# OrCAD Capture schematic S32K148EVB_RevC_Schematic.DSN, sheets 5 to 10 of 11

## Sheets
5 05. OPEN SDA: size D; company: Freescale Semiconductor; note: SCH-29642 PDF: SPF-29642
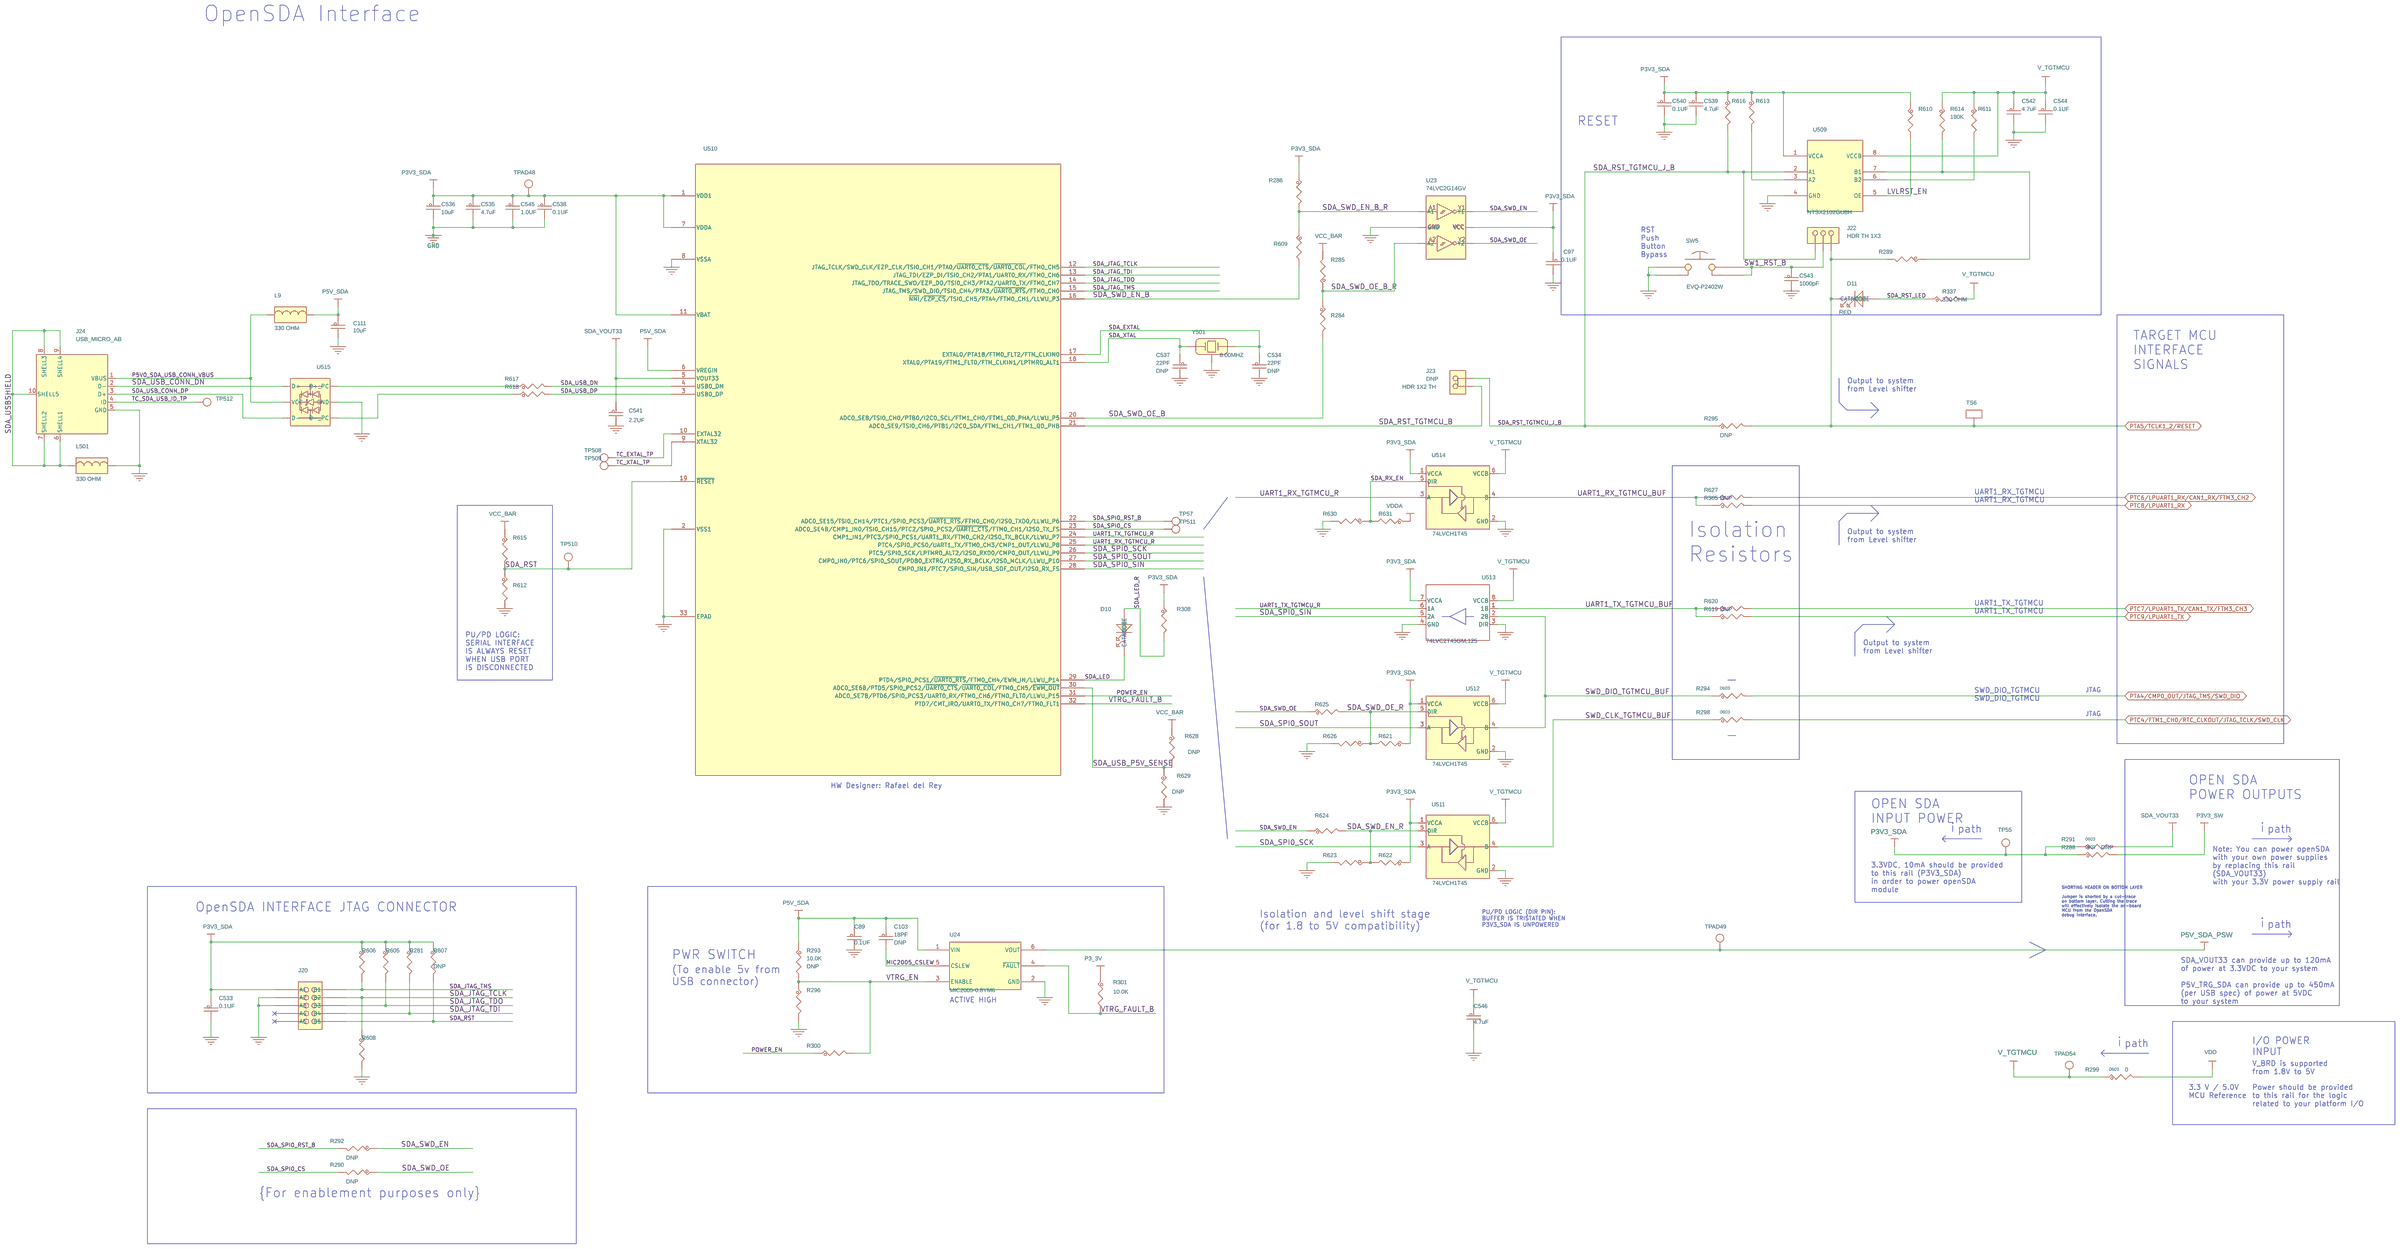
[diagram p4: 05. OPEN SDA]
6 06. ETHERNET: size C; note: SCH-29642 PDF: SPF-29642
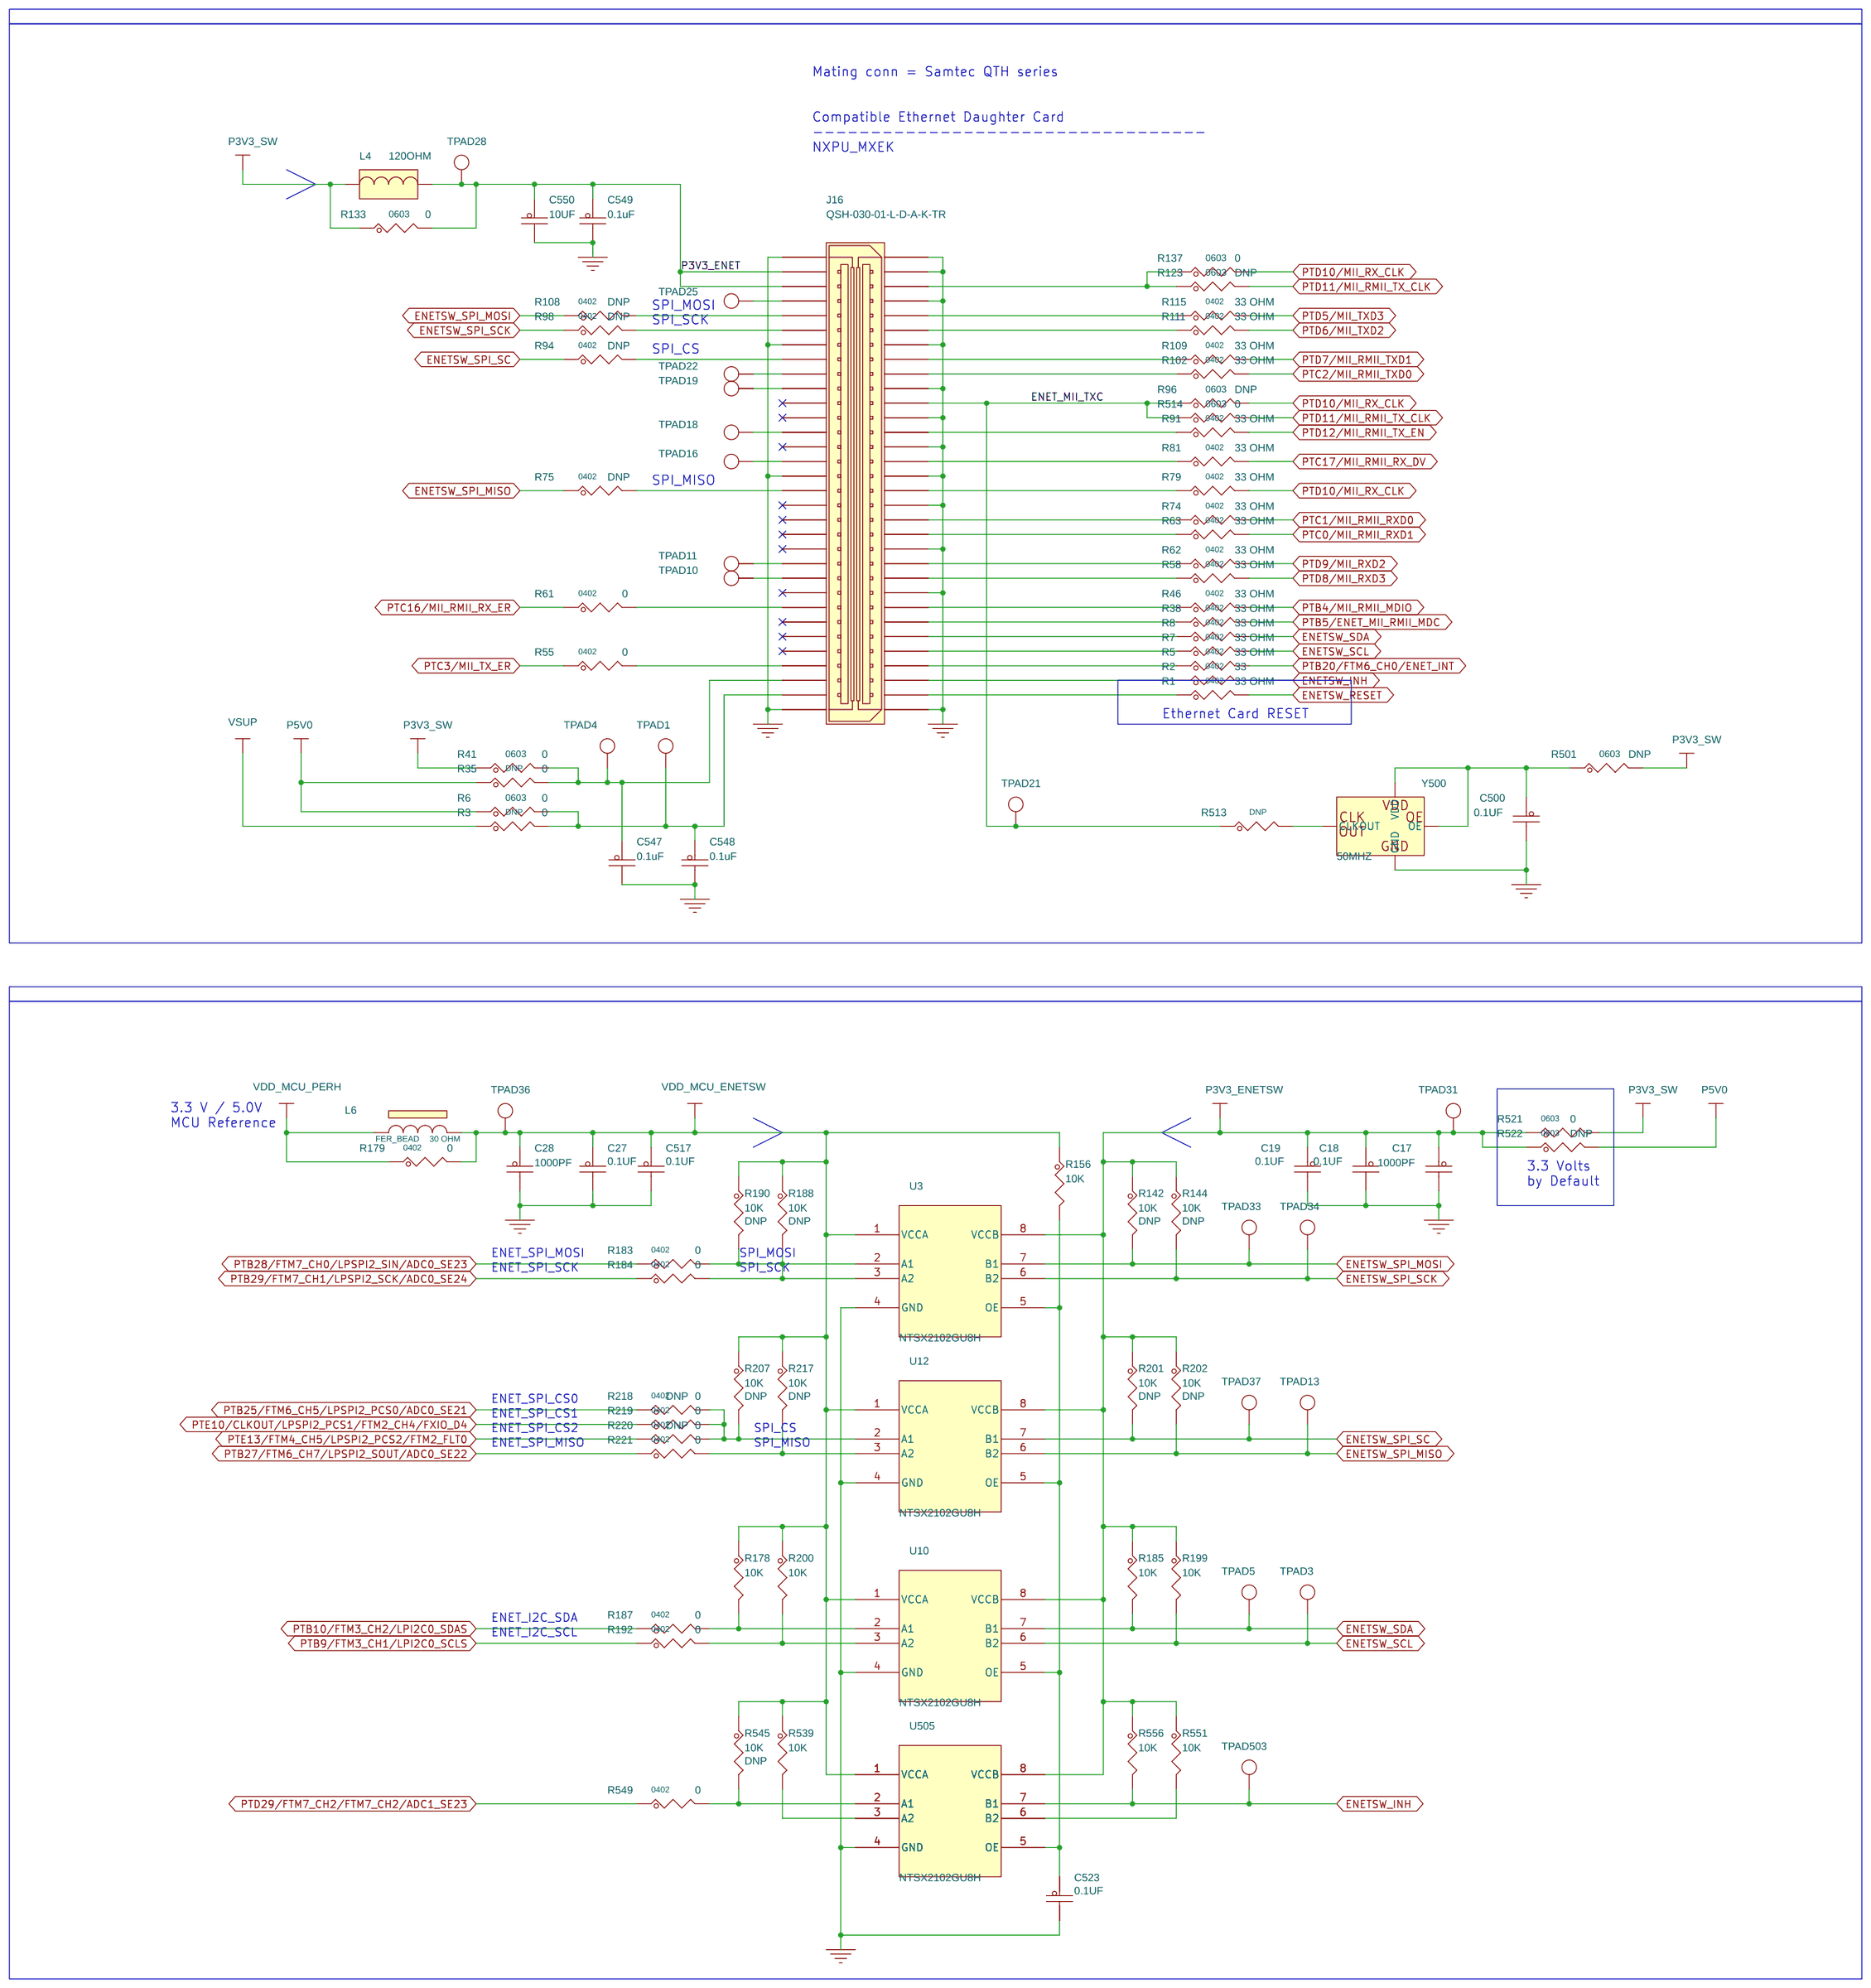
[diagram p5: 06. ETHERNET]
7 07. HYPERFLASH: size B; note: SCH-29642 PDF: SPF-29642
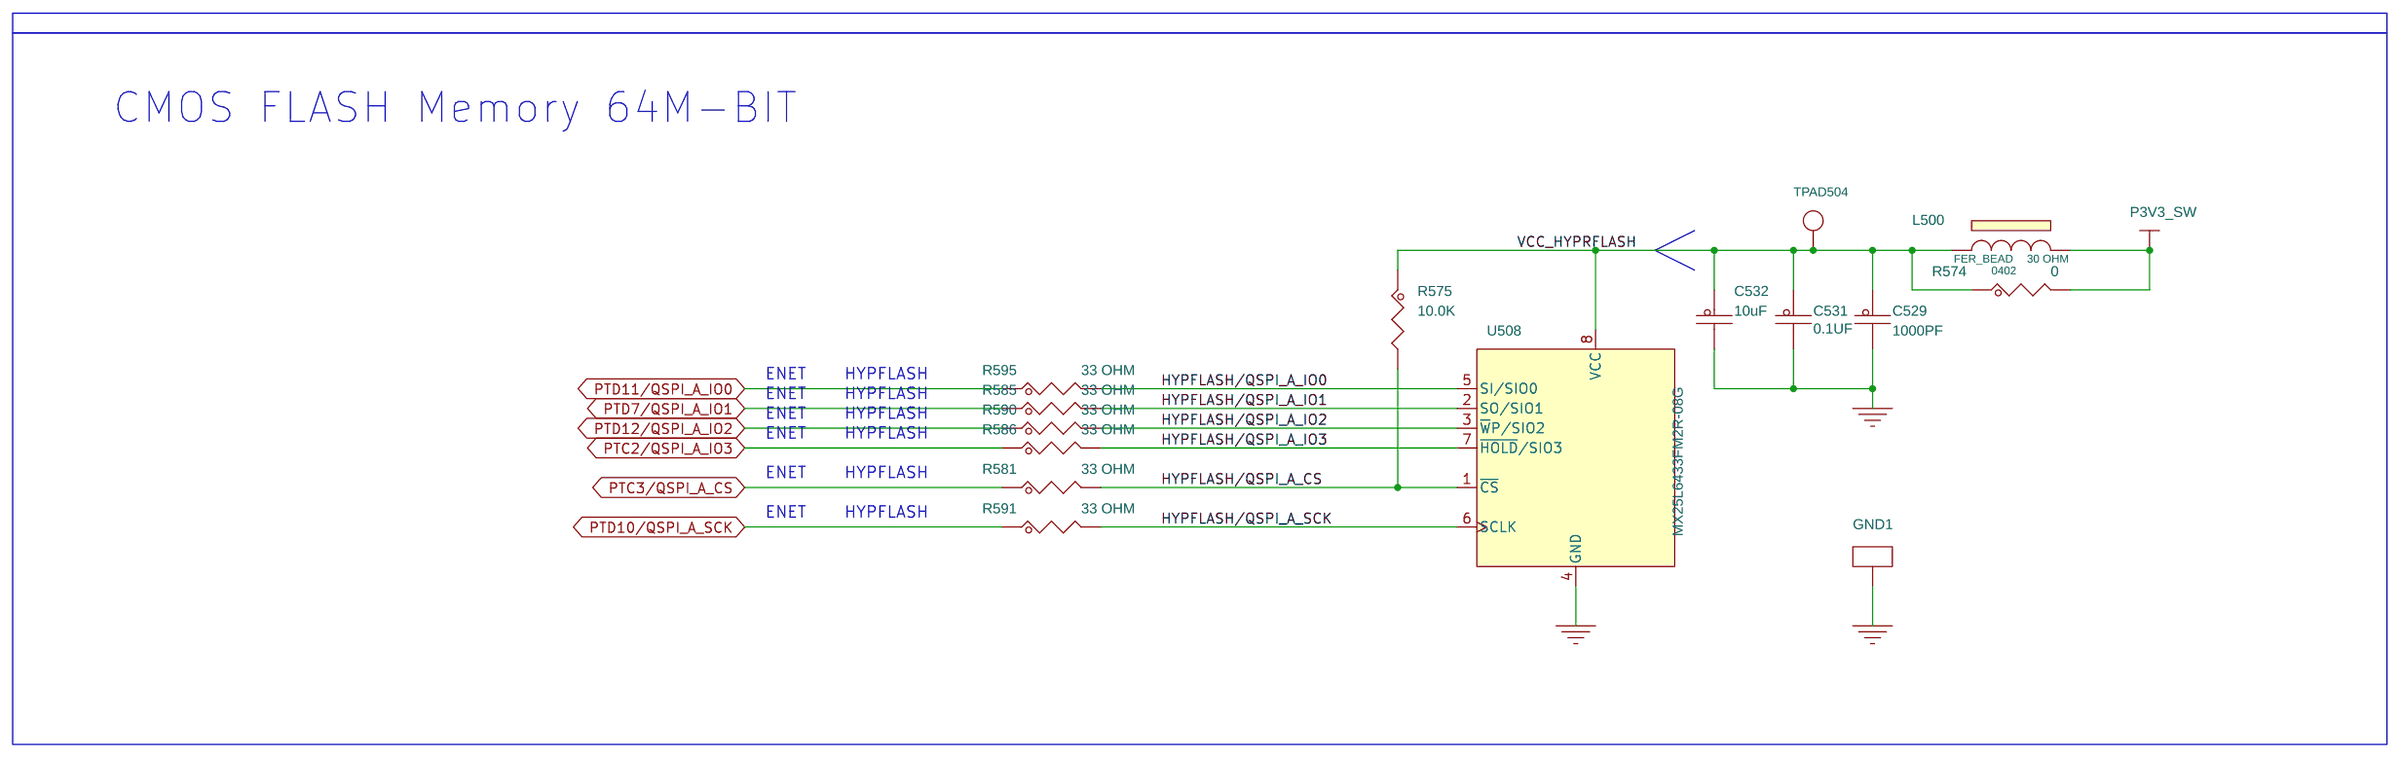
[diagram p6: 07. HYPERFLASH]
8 10. TOUCHPAD: size B; note: SCH-29642 PDF: SPF-29642
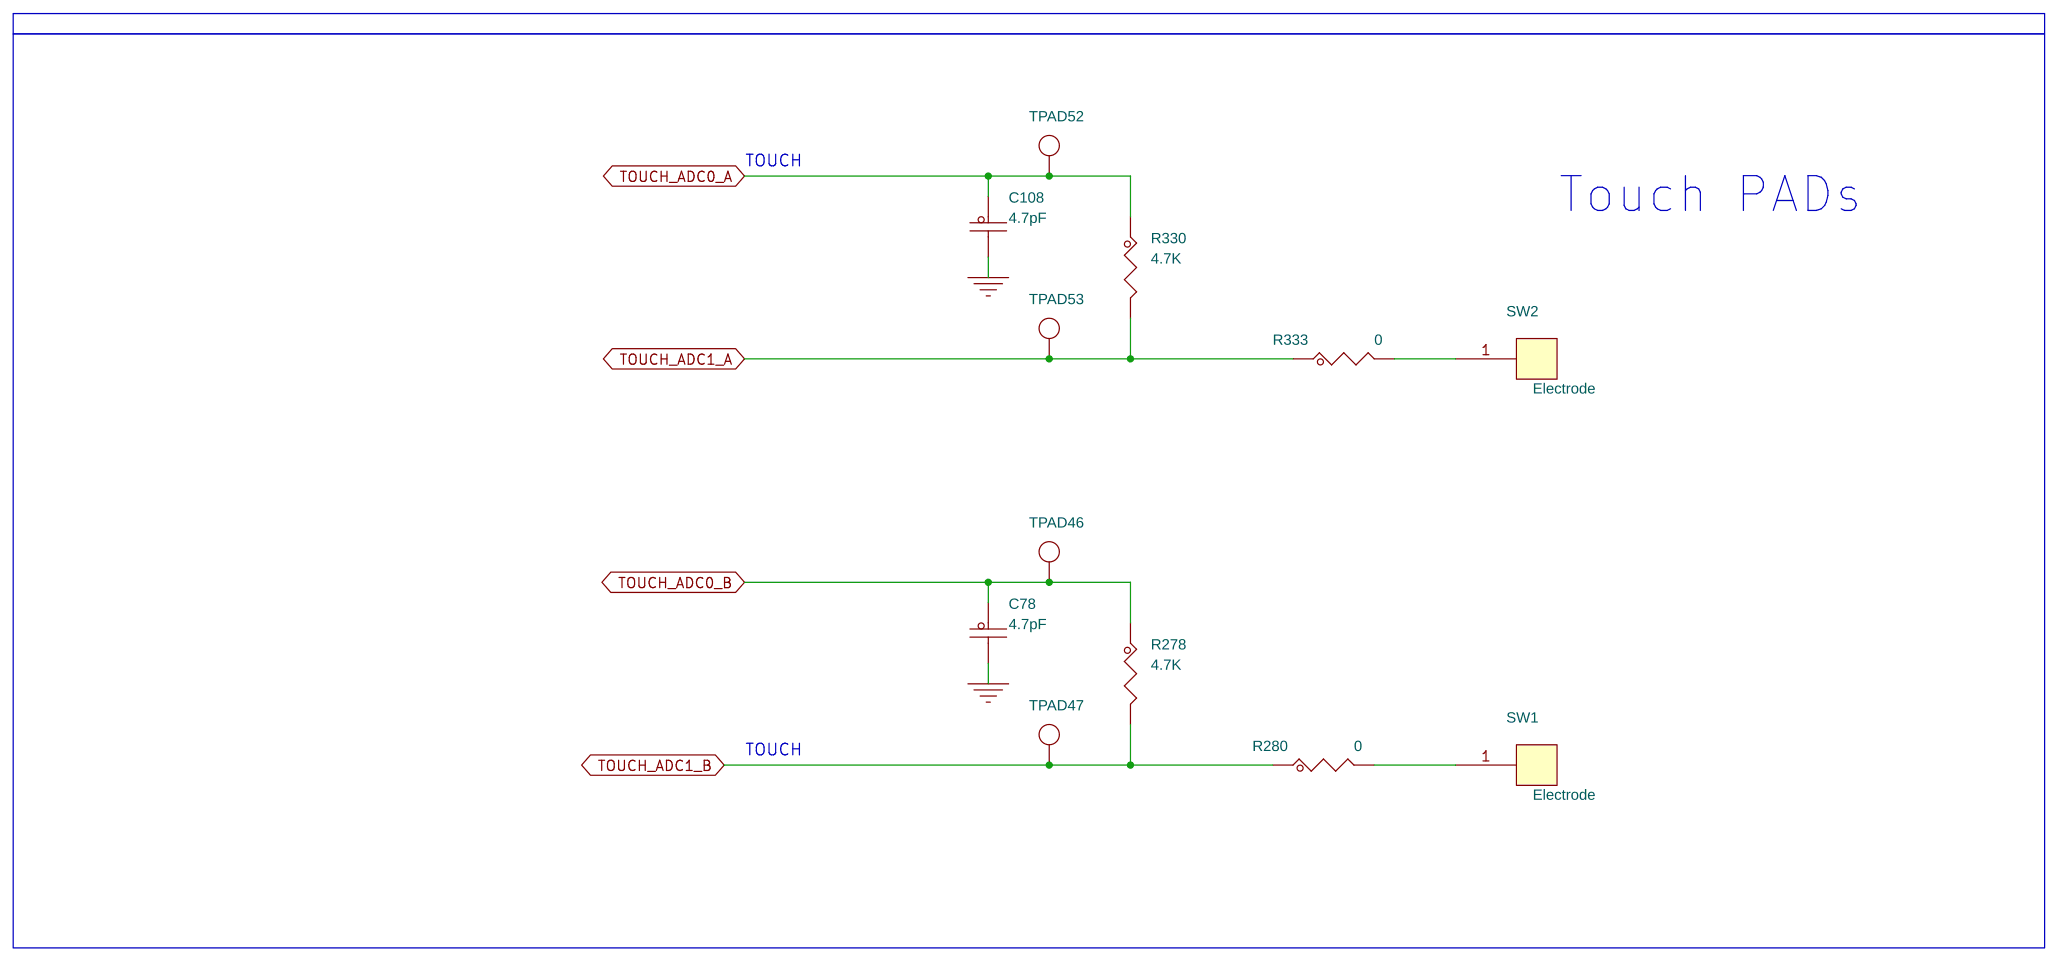
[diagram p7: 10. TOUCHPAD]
9 11. USER PHERP: size B; company: Freescale Semiconductor; note: SCH-29642 PDF: SPF-29642
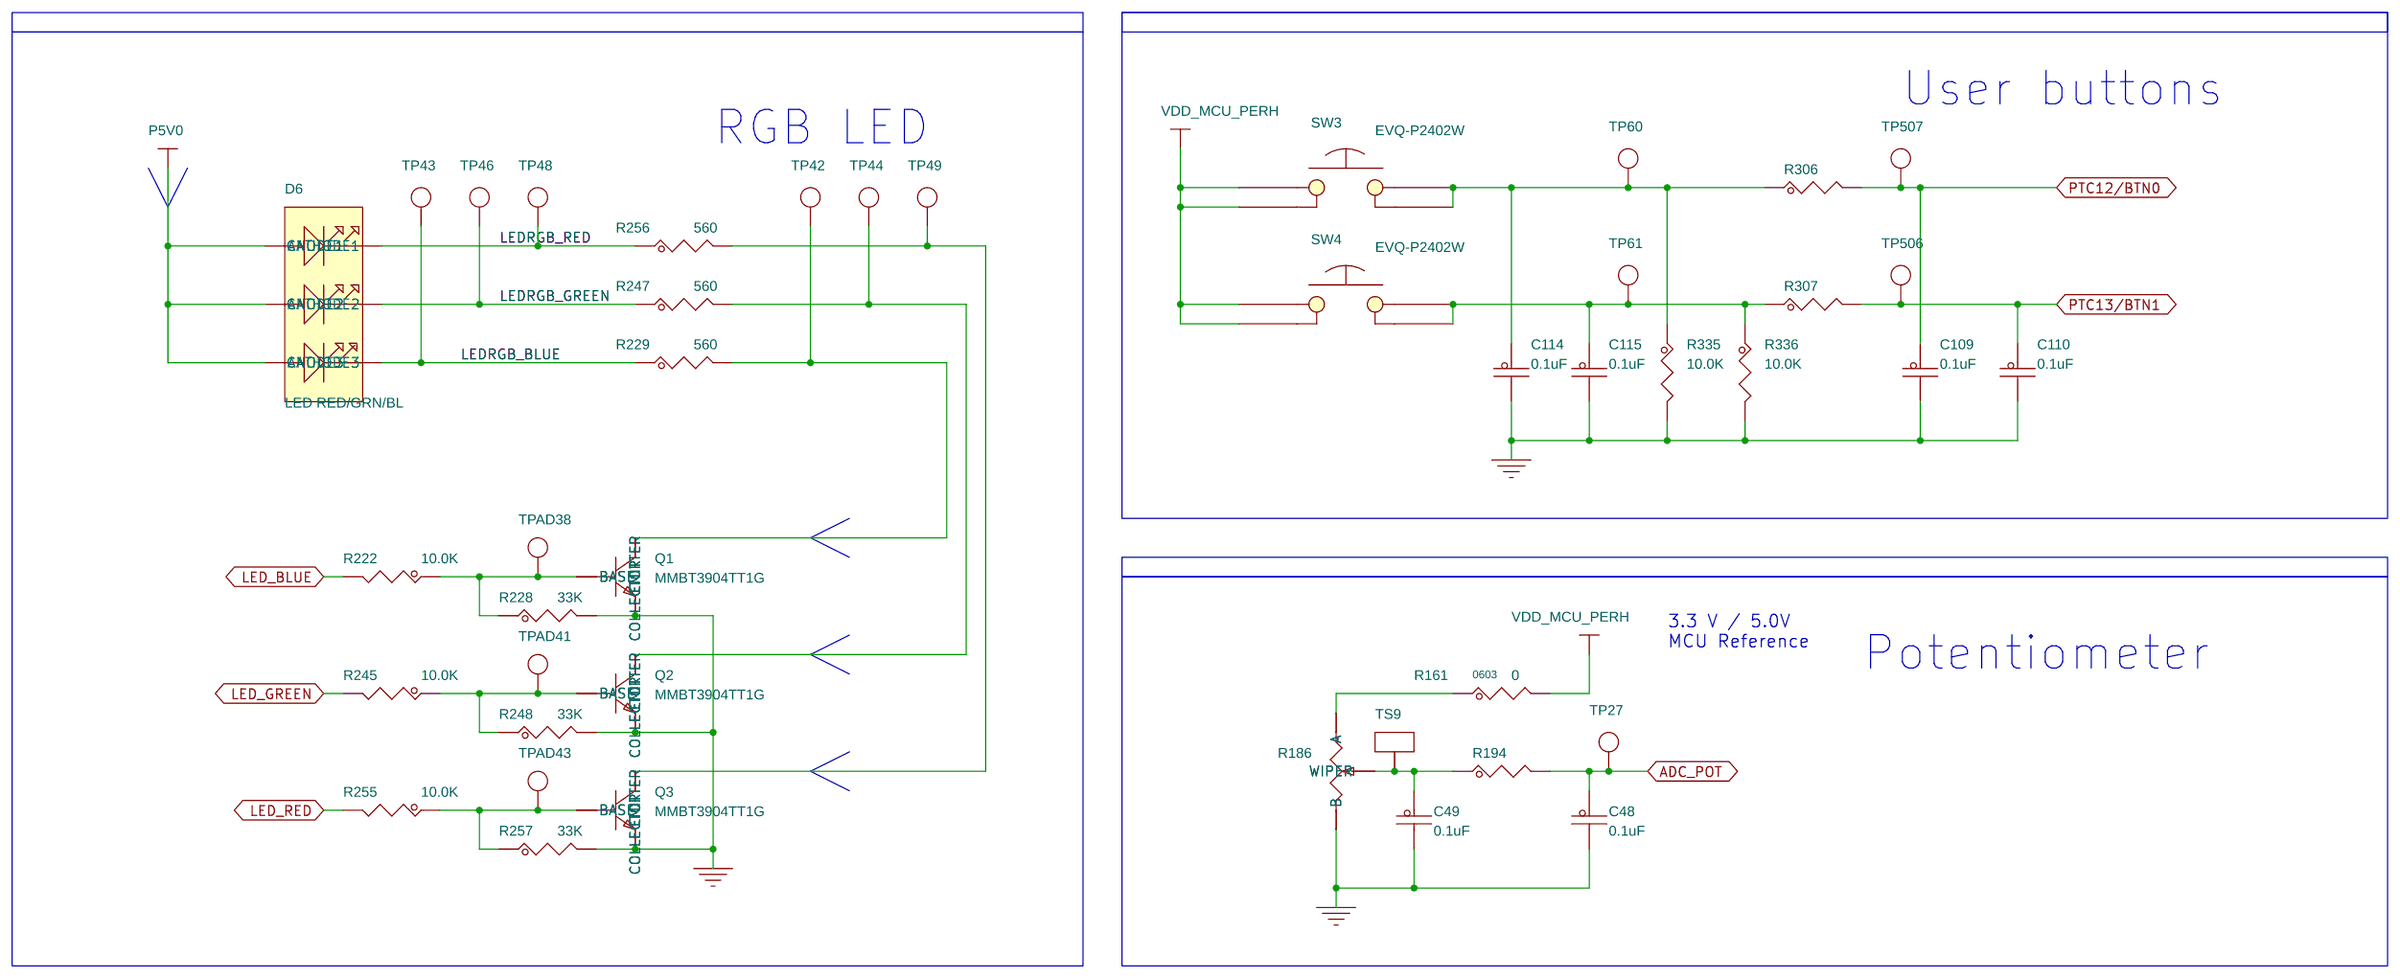
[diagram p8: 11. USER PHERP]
10 01. TITLE/NOTE: company: Freescale Semiconductor; note: SCH-29642 PDF: SPF-29642

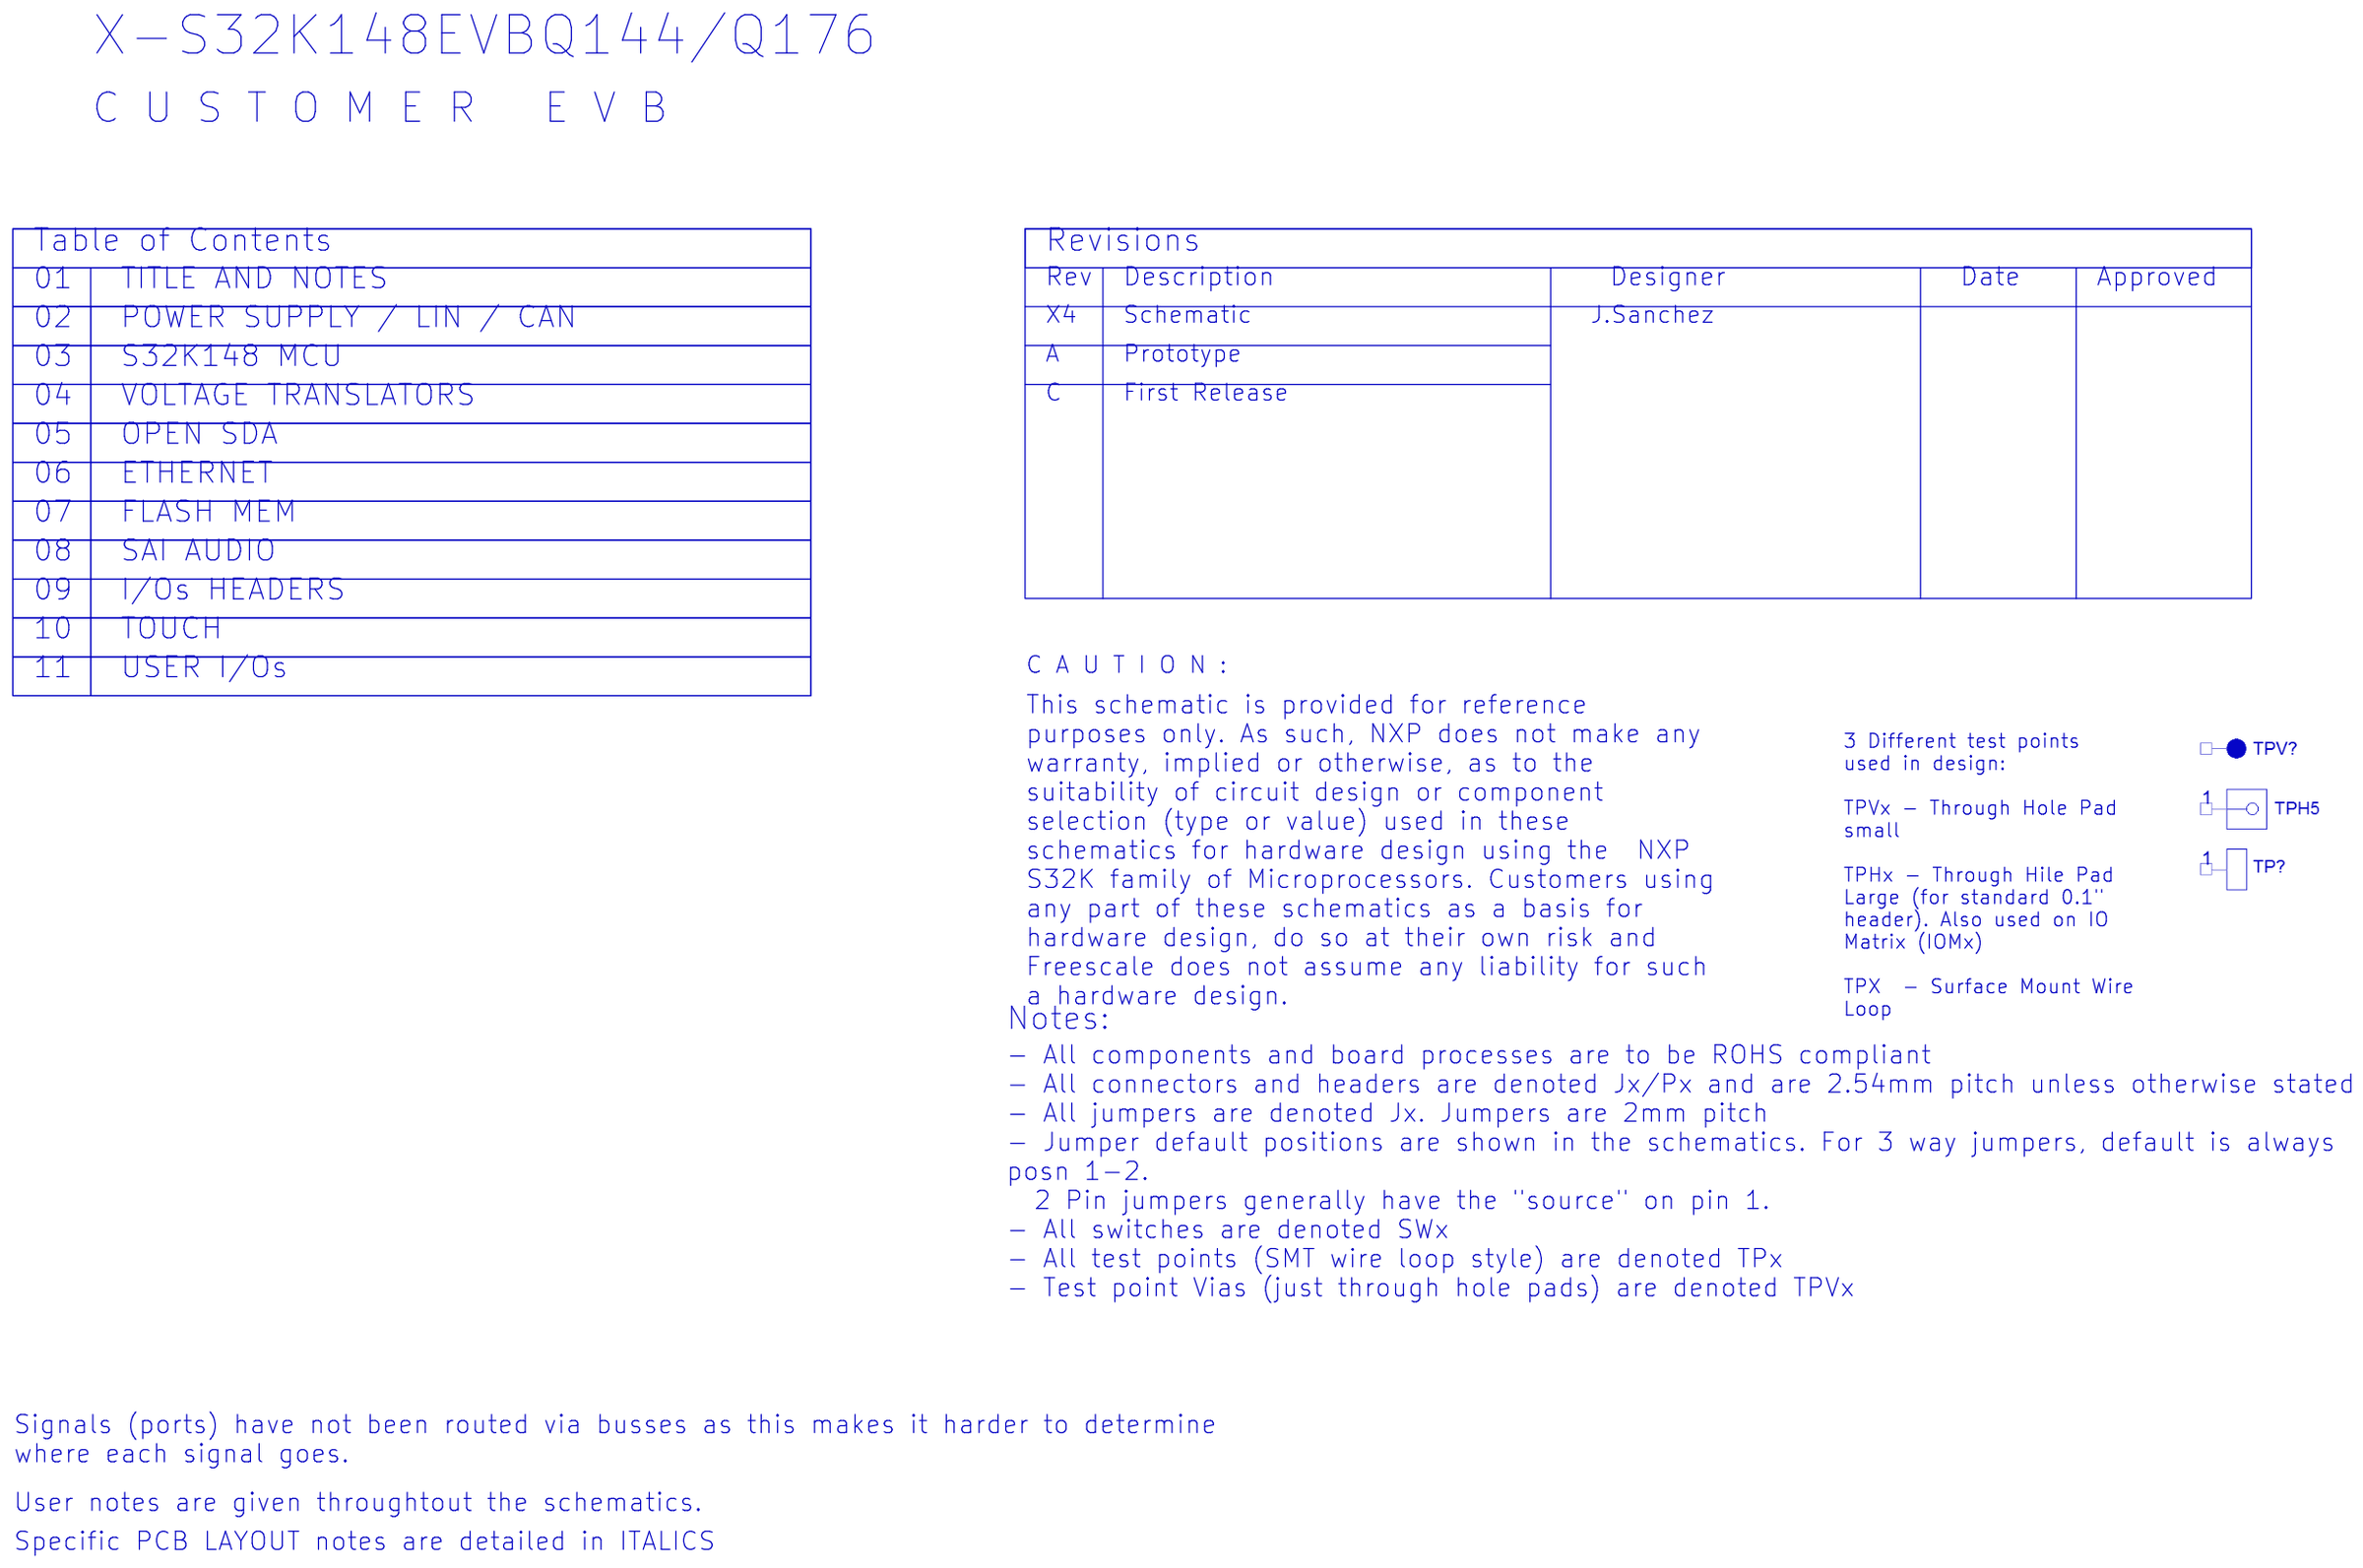
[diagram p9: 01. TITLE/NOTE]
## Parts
sheet 05. OPEN SDA
C89  0.1UF  [CC0402_25]
C97  0.1UF  [CC0402_25]
C103  18PF  [CC0603_OV]
C111  10uF  [CC0402_25]
C533  0.1UF  [CC0402_25]
C534  22PF  [CC0402_25]
C535  4.7uF  [CC0402_25]
C536  10uF  [CC0603_OV]
C537  22PF  [CC0402_25]
C538  0.1UF  [CC0402_25]
C539  4.7uF  [CC0402_25]
C540  0.1UF  [CC0402_25]
C541  2.2UF  [CC0603_OV]
C542  4.7uF  [CC0402_25]
C543  1000pF  [CC0402_25]
C544  0.1UF  [CC0402_25]
C545  1.0UF  [CC0402_25]
C546  4.7uF  [CC0402_25]
D10  LED GREEN  [LED_0603]
D11  RED  [LED_0603]
J20  HDR 2X5  [CON_2RH_10_50]
J22  HDR TH 1X3  [HDR103]
J23  HDR 1X2 TH  [SH_HDR102_BOTTOM]
J24  USB_MICRO_AB  [con_microab_10f_25_sm_ra]
L9  330 OHM  [ind_1608]
L501  330 OHM  [ind_1608]
R281  10.0K  [RC0402_25]
R284  0  [RC0402_25]
R285  10.0K  [RC0402_25]
R286  10.0K  [RC0402_25]
R288  0  [RC0603]
R289  0  [RC0402_25]
R290  0  [RC0402_25]
R291  0  [RC0603]
R292  0  [RC0402_25]
R293  10.0K  [RC0402_25]
R294  0  [RC0603]
R295  0  [RC0402_25]
R296  15K  [RC0402_25]
R298  0  [RC0603]
R299  0  [RC0603]
R300  1.0K  [RC0402_25]
R301  10.0K  [RC0402_25]
R305  0  [RC0402_25]
R308  220  [RC0603_OV]
R337  330 OHM  [RC0402_25]
R605  10.0K  [RC0402_25]
R606  10.0K  [RC0402_25]
R607  10.0K  [RC0402_25]
R608  10.0K  [RC0402_25]
R609  0  [RC0402_25]
R610  4.7K  [RC0402_25]
R611  10.0K  [RC0402_25]
R612  10.0K  [RC0402_25]
R613  10.0K  [RC0402_25]
R614  180K  [RC0402_25]
R615  4.7K  [RC0402_25]
R616  10.0K  [RC0402_25]
R617  33  [RC0402_25]
R618  33  [RC0402_25]
R619  0  [RC0402_25]
R620  0  [RC0402_25]
R621  4.7K  [RC0402_25]
R622  4.7K  [RC0402_25]
R623  10.0K  [RC0402_25]
R624  0  [RC0402_25]
R625  0  [RC0402_25]
R626  10.0K  [RC0402_25]
R627  0  [RC0402_25]
R628  4.7K  [RC0402_25]
R629  10.0K  [RC0402_25]
R630  10.0K  [RC0402_25]
R631  4.7K  [RC0402_25]
SW5  EVQ-P2402W  [sw4_spst_4p8X3p6_2p5]
TP55  TPAD_030  [TPAD_030]
TP57  TPAD_030  [TPAD_030]
TP508  TPAD_030  [TPAD_030]
TP509  TPAD_030  [TPAD_030]
TP510  TPAD_030  [TPAD_030]
TP511  TPAD_030  [TPAD_030]
TP512  TPAD_030  [TPAD_030]
TPAD48  TPAD_030  [TPAD_030]
TPAD49  TPAD_030  [TPAD_030]
TPAD54  TPAD_030  [TPAD_030]
TS6  TESTLOOP  [testpoint_135_070mil]
U23  74LVC2G14GV  [SC74_6P_1P7X3P1]
U24  MIC2005-0.8YM6  [SOT23-6_a]
U509  NTSX2102GU8H  [xqfn8_1p45x1p25mm]
U510  MK20DX128VFM5  [QFN32_S142EP]
U511  74LVCH1T45  [udfn6_1x1p5mm]
U512  74LVCH1T45  [udfn6_1x1p5mm]
U513  74LVC2T45GM,125  [qfn8_1p6x1p6mm]
U514  74LVCH1T45  [udfn6_1x1p5mm]
U515  RClamp0502A.TCT  [sot666]
Y501  8.00MHZ  [xtal3_3p35x1p45_sm]
sheet 06. ETHERNET
C17  1000PF  [CC0603_OV]
C18  0.1UF  [CC0603_OV]
C19  0.1UF  [CC0603_OV]
C27  0.1UF  [CC0603_OV]
C28  1000PF  [CC0603_OV]
C500  0.1UF  [CC0603]
C517  0.1UF  [CC0603_OV]
C523  0.1UF  [CC0603_OV]
C547  0.1uF  [CC0402_25]
C548  0.1uF  [CC0402_25]
C549  0.1uF  [CC0402_25]
C550  10UF  [CC0805_OV]
J16  QSH-030-01-L-D-A-K-TR  [CON_60S_QSH_SM_A]
L4  120OHM  [IND_0603]
L6  30 OHM  [IND_0402]
R1  33 OHM  [RC0402_25]
R2  33  [RC0402_25]
R3  0  [RC0603]
R5  33 OHM  [RC0402_25]
R6  0  [RC0603]
R7  33 OHM  [RC0402_25]
R8  33 OHM  [RC0402_25]
R35  0  [RC0603]
R38  33 OHM  [RC0402_25]
R41  0  [RC0603]
R46  33 OHM  [RC0402_25]
R55  0  [RC0402_25]
R58  33 OHM  [RC0402_25]
R61  0  [RC0402_25]
R62  33 OHM  [RC0402_25]
R63  33 OHM  [RC0402_25]
R74  33 OHM  [RC0402_25]
R75  0  [RC0402_25]
R79  33 OHM  [RC0402_25]
R81  33 OHM  [RC0402_25]
R91  33 OHM  [RC0402_25]
R94  0  [RC0402_25]
R96  0  [RC0603]
R98  0  [RC0402_25]
R102  33 OHM  [RC0402_25]
R108  0  [RC0402_25]
R109  33 OHM  [RC0402_25]
R111  33 OHM  [RC0402_25]
R115  33 OHM  [RC0402_25]
R123  0  [RC0603]
R133  0  [RC0603]
R137  0  [RC0603]
R142  10K  [RC0603_OV]
R144  10K  [RC0603_OV]
R156  10K  [RC0603_OV]
R178  10K  [RC0603_OV]
R179  0  [RC0402_25]
R183  0  [RC0402_25]
R184  0  [RC0402_25]
R185  10K  [RC0603_OV]
R187  0  [RC0402_25]
R188  10K  [RC0603_OV]
R190  10K  [RC0603_OV]
R192  0  [RC0402_25]
R199  10K  [RC0603_OV]
R200  10K  [RC0603_OV]
R201  10K  [RC0603_OV]
R202  10K  [RC0603_OV]
R207  10K  [RC0603_OV]
R217  10K  [RC0603_OV]
R218  0  [RC0402_25]
R219  0  [RC0402_25]
R220  0  [RC0402_25]
R221  0  [RC0402_25]
R501  0  [RC0603]
R513  0  [RC0603]
R514  0  [RC0603]
R521  0  [RC0603]
R522  0  [RC0603]
R539  10K  [RC0603_OV]
R545  10K  [RC0603_OV]
R549  0  [RC0402_25]
R551  10K  [RC0603_OV]
R556  10K  [RC0603_OV]
TPAD1  TPAD_030  [TPAD_030]
TPAD3  TPAD_030  [TPAD_030]
TPAD4  TPAD_030  [TPAD_030]
TPAD5  TPAD_030  [TPAD_030]
TPAD10  TPAD_030  [TPAD_030]
TPAD11  TPAD_030  [TPAD_030]
TPAD13  TPAD_030  [TPAD_030]
TPAD16  TPAD_030  [TPAD_030]
TPAD18  TPAD_030  [TPAD_030]
TPAD19  TPAD_030  [TPAD_030]
TPAD21  TPAD_030  [TPAD_030]
TPAD22  TPAD_030  [TPAD_030]
TPAD25  TPAD_030  [TPAD_030]
TPAD28  TPAD_030  [TPAD_030]
TPAD31  TPAD_030  [TPAD_030]
TPAD33  TPAD_030  [TPAD_030]
TPAD34  TPAD_030  [TPAD_030]
TPAD36  TPAD_030  [TPAD_030]
TPAD37  TPAD_030  [TPAD_030]
TPAD503  TPAD_030  [TPAD_030]
U3  NTSX2102GU8H  [xqfn8_1p45x1p25mm]
U10  NTSX2102GU8H  [xqfn8_1p45x1p25mm]
U12  NTSX2102GU8H  [xqfn8_1p45x1p25mm]
U505  NTSX2102GU8H  [xqfn8_1p45x1p25mm]
Y500  50MHZ  [XTLOSC4_SM]
sheet 07. HYPERFLASH
C529  1000PF  [CC0603_OV]
C531  0.1UF  [CC0603_OV]
C532  10uF  [CC0603_OV]
GND1  5006  [tp_th_063]
L500  30 OHM  [IND_0402]
R574  0  [RC0402_25]
R575  10.0K  [RC0603]
R581  33 OHM  [RC0402_25]
R585  33 OHM  [RC0402_25]
R586  33 OHM  [RC0402_25]
R590  33 OHM  [RC0402_25]
R591  33 OHM  [RC0402_25]
R595  33 OHM  [RC0402_25]
TPAD504  TPAD_030  [TPAD_030]
U508  MX25L6433FM2R-08G  [SO8_W]
sheet 10. TOUCHPAD
C78  4.7pF  [CC0603_OV]
C108  4.7pF  [CC0603_OV]
R278  4.7K  [RC0603_OV]
R280  0  [RC0603_OV]
R330  4.7K  [RC0603_OV]
R333  0  [RC0603_OV]
SW1  Electrode  [electrode_sq_15mm]
SW2  Electrode  [electrode_sq_15mm]
TPAD46  TPAD_030  [TPAD_030]
TPAD47  TPAD_030  [TPAD_030]
TPAD52  TPAD_030  [TPAD_030]
TPAD53  TPAD_030  [TPAD_030]
sheet 11. USER PHERP
C48  0.1uF  [CC0402_25]
C49  0.1uF  [CC0402_25]
C109  0.1uF  [CC0402_25]
C110  0.1uF  [CC0402_25]
C114  0.1uF  [CC0402_25]
C115  0.1uF  [CC0402_25]
D6  LED RED/GRN/BL  [led6_5x6mm]
Q1  MMBT3904TT1G  [sc_75]
Q2  MMBT3904TT1G  [sc_75]
Q3  MMBT3904TT1G  [sc_75]
R161  0  [RC0603]
R186  5K  [pot3_3352t]
R194  220  [RC0603_OV]
R222  10.0K  [RC0402_25]
R228  33K  [RC0402_25]
R229  560  [RC0603]
R245  10.0K  [RC0402_25]
R247  560  [RC0603]
R248  33K  [RC0402_25]
R255  10.0K  [RC0402_25]
R256  560  [RC0603]
R257  33K  [RC0402_25]
R306  220  [RC0603_OV]
R307  220  [RC0603_OV]
R335  10.0K  [RC0402_25]
R336  10.0K  [RC0402_25]
SW3  EVQ-P2402W  [sw4_spst_4p8X3p6_2p5]
SW4  EVQ-P2402W  [sw4_spst_4p8X3p6_2p5]
TP27  TPAD_028  [TPAD_028]
TP42  TPAD_028  [TPAD_028]
TP43  TPAD_028  [TPAD_028]
TP44  TPAD_028  [TPAD_028]
TP46  TPAD_028  [TPAD_028]
TP48  TPAD_028  [TPAD_028]
TP49  TPAD_028  [TPAD_028]
TP60  TPAD_028  [TPAD_028]
TP61  TPAD_028  [TPAD_028]
TP506  TPAD_028  [TPAD_028]
TP507  TPAD_028  [TPAD_028]
TPAD38  TPAD_030  [TPAD_030]
TPAD41  TPAD_030  [TPAD_030]
TPAD43  TPAD_030  [TPAD_030]
TS9  TESTLOOP  [testpoint_135_070mil]

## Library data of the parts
C89 C97 C533 C538 C540 C544 = CAP_NP: CAP CER 0.1UF 10V 10% X5R 0402; AGILE_PN: 150-75634; CAD_APPROVED: Yes; FPLIST: CC0402_25,CC0402_HD,0402_CC; HEIGHT: 0.64MM; MFG_NAME01: KEMET; MFG_PN01: C0402C104K8PAC; PRIORITY_PN: 021-00169; ROHS: Yes; SIGNAL_MODEL: DEFAULT_CAPACITOR_100000pF_2_1; TOL: 10%; Tolerance: 10%; VOLTAGE: 10V
C103 = CAP_NP: CAP CER 18PF 50V 5% C0G 0603; AGILE_PN: 150-75116; ASSY_OPT: DNP; CAD_APPROVED: Yes; FPLIST: CC0603_OV,CC0603,0603_CC; HEIGHT: 0.90MM; MFG_NAME01: YAGEO AMERICA; MFG_PN01: CC0603JRNPO9BN180; PRIORITY_PN: 021-00320; ROHS: Yes; SIGNAL_MODEL: DEFAULT_CAPACITOR_18.000000pF_2_1; TOL: 5%; Tolerance: 5%; VOLTAGE: 50V
C111 = CAP_NP: CAP CER 10uF 10V 20% X5R 0402; AGILE_PN: 150-79255; CAD_APPROVED: Yes; FPLIST: C0402_25,CC0402_HD,0402_CC; HEIGHT: 0.7MM; MFG_NAME01: SAMSUNG; MFG_PN01: CL05A106MP5NUNC; PRIORITY_PN: 021-00242; ROHS: Yes; SIGNAL_MODEL: DEFAULT_CAPACITOR_1e+06pF_2_1; Tolerance: 20%; VOLTAGE: 10V
C534 C537 = CAP_NP: CAP CER 22PF 50V 5% C0G 0402; AGILE_PN: 150-75266; ASSY_OPT: DNP; CAD_APPROVED: Yes; FPLIST: CC0402_25,CC0402_HD,0402_CC; HEIGHT: 0.635MM; MFG_NAME01: AVX; MFG_PN01: 04025A220JAT2A; PRIORITY_PN: 021-00234; ROHS: Yes; SIGNAL_MODEL: DEFAULT_CAPACITOR_22.000000pF_2_1; Tolerance: 5%; VOLTAGE: 50V
C535 C539 C542 C546 = CAP_NP: CAP CER 4.7UF 6.3V 20% X5R 0402; AGILE_PN: 150-78463; CAD_APPROVED: Yes; FPLIST: CC0402_25,CC0402_HD,0402_CC; HEIGHT: 0.65MM; MFG_NAME01: TDK; MFG_PN01: C1005X5R0J475M050BC; PRIORITY_PN: 021-00169; ROHS: Yes; SIGNAL_MODEL: DEFAULT_CAPACITOR_4.7e+06pF_2_1; TOL: 10%; Tolerance: 20%; VOLTAGE: 6.3V
C536 = CAP_NP: CAP CER 10uF 16V 20% X5R 0603; AGILE_PN: 150-79092; CAD_APPROVED: Yes; FPLIST: CC0603_OV,CC0603,0603_CC; HEIGHT: 1mm; MFG_NAME01: TAIYO YUDEN; MFG_PN01: EMK107BBJ106MA-T; ROHS: Yes; SIGNAL_MODEL: DEFAULT_CAPACITOR_1e+07pF_2_1; TOL: 10%; Tolerance: 20%; VOLTAGE: 16V
C541 = CAP_NP: CAP CER 2.2UF 10V 10% X7R 0603; AGILE_PN: 150-78564; CAD_APPROVED: Yes; FPLIST: CC0603_OV,CC0603,0603_CC; HEIGHT: 1.25MM; MFG_NAME01: TAIYO YUDEN; MFG_PN01: LMK107B7225KA-T; ROHS: Yes; SIGNAL_MODEL: DEFAULT_CAPACITOR_2.2e+06pF_2_1; Tolerance: 10%; VOLTAGE: 10V
C543 = CAP_NP: CAP CER 1000PF 50V 5% C0G 0402; AGILE_PN: 150-76334; CAD_APPROVED: Yes; FPLIST: CC0402_25,CC0402_HD,0402_CC; HEIGHT: 0.55MM; MFG_NAME01: MURATA; MFG_PN01: GRM1555C1H102JA01D; ROHS: Yes; Tolerance: 5%; VOLTAGE: 50V
C545 = CAP_NP: CAP CER 1.0UF 10V 10% X5R 0402; AGILE_PN: 150-75772; CAD_APPROVED: Yes; FPLIST: CC0402_25,CC0402_HD,0402_CC; HEIGHT: 0.6MM; MFG_NAME01: YAGEO AMERICA; MFG_PN01: CC0402KRX5R6BB105; PRIORITY_PN: 021-00242; ROHS: Yes; SIGNAL_MODEL: DEFAULT_CAPACITOR_1e+06pF_2_1; VOLTAGE: 10V
D10 = LED: LED GRN SGL 20MA 0603; AGILE_PN: 370-76565; CAD_APPROVED: Yes; HEIGHT: 0.67MM; MFG_NAME01: osram; MFG_PN01: LG L29K-G2J1-24-Z; ROHS: Yes
D11 = LED: LED ULTRA BRIGHT RED SGL 30MA 0603; AGILE_PN: 370-75079; CAD_APPROVED: Yes; HEIGHT: 0.9MM; MFG_NAME01: LITE ON; MFG_PN01: LTST-C190KRKT; ROHS: Yes
J20 = CONN_HDR_5X2: CONN,HEAD,2X5,STR,50/50 CON-2RH-10-50; AGILE_PN: 210-07961-00; CAD_APPROVED: Yes; FPLIST: CON_2RH_10_50,con_2rh_10_50_nsp; HEIGHT: 3.91 MM; MFG_NAME01: SAMTEC; MFG_PN01: FTS-105-01-F-D; ROHS: Yes
J22 = CONN_HDR_3X1: HDR 1x3 TH 100MIL SP 343H AU 100L; AGILE_PN: 210-80734; CAD_APPROVED: Yes; HEIGHT: 8.72MM; MFG_NAME01: SAMTEC; MFG_PN01: TSW-103-07-F-S; ROHS: Yes
J23 = CONN_HDR_2X1: HDR 1X2 TH 100MIL SP 339H AU 98L; AGILE_PN: 210-75439; ASSY_OPT: DNP; CAD_APPROVED: YES; FPLIST: HDR102,SH_HDR102_BOTTOM; HEIGHT: 8.71 MM; MFG_NAME01: SAMTEC; MFG_PN01: TSW-102-07-G-S; PRIORITY_PN: 028-00556; ROHS: Yes
J24 = MICRO_USB_CONN_10PIN: CON 5 USB_MICRO_AB_RECEPTACLE RA SKT SMT 0.65MM SP 122H AU; AGILE_PN: 211-78945; CAD_APPROVED: Yes; HEIGHT: 3.1MM; MFG_NAME01: molex; MFG_PN01: 0475900001; ROHS: Yes
L9 L501 = BEAD: IND FER BEAD 330OHM@100MHZ 1.7A 0603; AGILE_PN: 180-78156; CAD_APPROVED: Yes; FPLIST: ind_1608,0603_CC; HEIGHT: 0.95MM; MFG_NAME01: TDK; MFG_PN01: MPZ1608S331A; PART_TYPE: FERRITE\BEAD; ROHS: Yes; Tolerance: 25%
R281 R605 R606 R608 R612 = RES: RES MF 10.0K 1/16W 1% AEC-Q200 0402; AGILE_PN: 470-75416; CAD_APPROVED: Yes; FPLIST: RC0402_25,RC0402_HD,0402_CC; HEIGHT: 0.4MM; MFG_NAME01: KOA SPEER; MFG_PN01: RK73H1ETTP1002F; PRIORITY_PN: 006-00552; ROHS: Yes; SIGNAL_MODEL: DEFAULT_RESISTOR_10000OHM_2_1; Tolerance: 1%
R284 R289 R609 R624 R625 = RES: RES MF ZERO OHM 1/16W -- AEC-Q200 0402; AGILE_PN: 470-80742; CAD_APPROVED: Yes; FPLIST: RC0402_25,RC0402_HD,0402_CC; HEIGHT: 0.45 MM; MFG_NAME01: VISHAY INTERTECHNOLOGY; MFG_PN01: CRCW04020000Z0ED; PRIORITY_PN: 006-00559; ROHS: Yes; SIGNAL_MODEL: DEFAULT_RESISTOR_0.001OHM_2_1; VOLTAGE: 1/16W
R285 R286 R611 R613 R616 R623 R626 R630 = RES: RES MF 10.0K 1/16W 1% AEC-Q200 0402; AGILE_PN: 470-75416; CAD_APPROVED: Yes; FPLIST: RC0402_25,RC0402_HD,0402_CC; HEIGHT: 0.4MM; MFG_NAME01: KOA SPEER; MFG_PN01: RK73H1ETTP1002F; PRIORITY_PN: 006-00552; ROHS: Yes; SIGNAL_MODEL: DEFAULT_RESISTOR_10000OHM_2_1; TOL: 5%; Tolerance: 1%
R3 R35 R96 R123 R288 R501 R513 R522 = RES: RES MF ZERO OHM 1/10W -- AEC-Q200 0603; AGILE_PN: 470-75407; ASSY_OPT: DNP; CAD_APPROVED: Yes; FPLIST: RC0603_OV,RC0603,R603-X2,0603_CC; HEIGHT: 0.6MM; MFG_NAME01: KOA SPEER; MFG_PN01: RK73Z1JTTD; PCKG: 0603; ROHS: Yes; Tolerance: 1%
R290 R292 = RES: RES MF ZERO OHM 1/16W -- AEC-Q200 0402; AGILE_PN: 470-80742; ASSY_OPT: DNP; CAD_APPROVED: Yes; FPLIST: RC0402_25,RC0402_HD,0402_CC; HEIGHT: 0.45 MM; MFG_NAME01: VISHAY INTERTECHNOLOGY; MFG_PN01: CRCW04020000Z0ED; PRIORITY_PN: 006-00559; ROHS: Yes; SIGNAL_MODEL: DEFAULT_RESISTOR_0.001OHM_2_1; VOLTAGE: 1/16W
R6 R41 R133 R137 R161 R291 R294 R298 R299 R514 R521 = RES: RES MF ZERO OHM 1/10W -- AEC-Q200 0603; AGILE_PN: 470-75407; CAD_APPROVED: Yes; FPLIST: RC0603_OV,RC0603,R603-X2,0603_CC; HEIGHT: 0.6MM; MFG_NAME01: KOA SPEER; MFG_PN01: RK73Z1JTTD; PCKG: 0603; ROHS: Yes; Tolerance: 1%
R293 = RES: RES MF 10.0K 1/16W 1% AEC-Q200 0402; AGILE_PN: 470-75416; ASSY_OPT: DNP; CAD_APPROVED: Yes; FPLIST: RC0402_25,RC0402_HD,0402_CC; HEIGHT: 0.4MM; MFG_NAME01: KOA SPEER; MFG_PN01: RK73H1ETTP1002F; PRIORITY_PN: 006-00552; ROHS: Yes; SIGNAL_MODEL: DEFAULT_RESISTOR_10000OHM_2_1; TOL: 1%; Tolerance: 1%
R295 R305 R619 = RES: RES MF ZERO OHM 1/16W -- AEC-Q200 0402; AGILE_PN: 470-80742; ASSY_OPT: DNP; CAD_APPROVED: Yes; FPLIST: RC0402_25,RC0402_HD,0402_CC; HEIGHT: 0.45 MM; MFG_NAME01: VISHAY INTERTECHNOLOGY; MFG_PN01: CRCW04020000Z0ED; PRIORITY_PN: 006-00559; ROHS: Yes; SIGNAL_MODEL: DEFAULT_RESISTOR_0.001OHM_2_1; TOL: 5%; VOLTAGE: 1/16W
R296 = RES: RES MF 15K  1/16W 1% 0402; AGILE_PN: 470-30965; CAD_APPROVED: Yes; FPLIST: RC0402_25,RC0402_HD,0402_CC; HEIGHT: 0.40 MM; MFG_NAME01: KOA SPEER; MFG_PN01: RK73H1ETTP1502F; ROHS: Yes; SIGNAL_MODEL: DEFAULT_RESISTOR_15000OHM_2_1; TOL: 1%; Tolerance: 1%
R300 = RES: RES MF 1.0K 1/16W 1% 0402; AGILE_PN: 470-76037; CAD_APPROVED: Yes; FPLIST: RC0402_25,RC0402_HD,RC0402_X2,0402_CC; HEIGHT: 0.4MM; MFG_NAME01: YAGEO AMERICA; MFG_PN01: RC0402FR-071KL; PRIORITY_PN: 006-00553; ROHS: Yes; SIGNAL_MODEL: DEFAULT_RESISTOR_1000.000000OHM_2_1; TOL: 1%; Tolerance: 1%; VOLTAGE: 1/16W
R222 R245 R255 R301 R335 R336 = RES: RES MF 10.0K 1/16W 1% AEC-Q200 0402; AGILE_PN: 470-75416; CAD_APPROVED: Yes; FPLIST: RC0402_25,RC0402_HD,0402_CC; HEIGHT: 0.4MM; MFG_NAME01: KOA SPEER; MFG_PN01: RK73H1ETTP1002F; PRIORITY_PN: 006-00552; ROHS: Yes; SIGNAL_MODEL: DEFAULT_RESISTOR_10000OHM_2_1; TOL: 1%; Tolerance: 1%
R308 = RES: RES MF 220 OHM 1/10W 5% 0603; AGILE_PN: 470-30297; CAD_APPROVED: Yes; FPLIST: RC0603_OV,RC0603,0603_CC; HEIGHT: 0.6MM; MFG_NAME01: KOA SPEER; MFG_PN01: RK73B1JTTD221J; ROHS: Yes; SIGNAL_MODEL: DEFAULT_RESISTOR_220.000000OHM_2_1; Tolerance: 5%
R337 = RES: RES MF 330 OHM 1/16W 1% 0402; AGILE_PN: 470-80566; CAD_APPROVED: Yes; FPLIST: RC0402_25,RC0402_HD,0402_CC; HEIGHT: 0.4MM; MFG_NAME01: WALSIN TECHNOLOGY CORP.; MFG_PN01: WR04X3300FTL; ROHS: Yes; Tolerance: 1%
R607 R629 = RES: RES MF 10.0K 1/16W 1% AEC-Q200 0402; AGILE_PN: 470-75416; ASSY_OPT: DNP; CAD_APPROVED: Yes; FPLIST: RC0402_25,RC0402_HD,0402_CC; HEIGHT: 0.4MM; MFG_NAME01: KOA SPEER; MFG_PN01: RK73H1ETTP1002F; PRIORITY_PN: 006-00552; ROHS: Yes; SIGNAL_MODEL: DEFAULT_RESISTOR_10000OHM_2_1; Tolerance: 1%
R610 R615 R621 R622 R631 = RES: RES MF 4.7K 1/16W 5% 0402; AGILE_PN: 470-75626; CAD_APPROVED: Yes; FPLIST: RC0402_25,RC0402_HD,0402_CC; HEIGHT: 0.41mm; MFG_NAME01: KOA SPEER; MFG_PN01: RK73B1ETTP472J; ROHS: Yes; SIGNAL_MODEL: DEFAULT_RESISTOR_4700OHM_2_1; TOL: 1%; Tolerance: 5%
R614 = RES: RES MF 180K  1/16W 1% 0402; AGILE_PN: 470-31088; CAD_APPROVED: Yes; FPLIST: RC0402_25,RC0402_HD,0402_CC; HEIGHT: 0.40 MM; MFG_NAME01: KOA SPEER; MFG_PN01: RK73H1ETTP1803F; ROHS: Yes; SIGNAL_MODEL: DEFAULT_RESISTOR_180000OHM_2_1; Tolerance: 1%
R617 R618 = RES: RES MF 33.0 OHM 1/16W 1% 0402; AGILE_PN: 470-75790; CAD_APPROVED: Yes; FPLIST: RC0402_25,RC0402_HD,RC0402_X2,0402_CC; HEIGHT: 0.4MM; MFG_NAME01: THYE MING TECH CO LTD; MFG_PN01: CR-02FL6---33R; PRIORITY_PN: 006-00556; ROHS: Yes; SIGNAL_MODEL: DEFAULT_RESISTOR_33.000000OHM_2_1; Tolerance: 1%
R620 R627 = RES: RES MF ZERO OHM 1/16W -- AEC-Q200 0402; AGILE_PN: 470-80742; CAD_APPROVED: Yes; FPLIST: RC0402_25,RC0402_HD,0402_CC; HEIGHT: 0.45 MM; MFG_NAME01: VISHAY INTERTECHNOLOGY; MFG_PN01: CRCW04020000Z0ED; PRIORITY_PN: 006-00559; ROHS: Yes; SIGNAL_MODEL: DEFAULT_RESISTOR_0.001OHM_2_1; TOL: 5%; VOLTAGE: 1/16W
R628 = RES: RES MF 4.7K 1/16W 5% 0402; AGILE_PN: 470-75626; ASSY_OPT: DNP; CAD_APPROVED: Yes; FPLIST: RC0402_25,RC0402_HD,0402_CC; HEIGHT: 0.41mm; MFG_NAME01: KOA SPEER; MFG_PN01: RK73B1ETTP472J; ROHS: Yes; SIGNAL_MODEL: DEFAULT_RESISTOR_4700OHM_2_1; TOL: 1%; Tolerance: 5%
SW3-SW5 = EDGE_MOUNT_PB_SW_2: SW SPST PB NO 0.02A 15V SMT; AGILE_PN: 510-77992; CAD_APPROVED: Yes; HEIGHT: 2.7 MM; MFG_NAME01: Panasonic; ROHS: Yes
TP55 TP57 TP508-TP512 TPAD1 TPAD3-TPAD5 TPAD10 TPAD11 TPAD13 TPAD16 TPAD18 TPAD19 TPAD21 TPAD22 TPAD25 TPAD28 TPAD31 TPAD33 TPAD34 TPAD36-TPAD38 TPAD41 TPAD43 TPAD46-TPAD49 TPAD52-TPAD54 TPAD503 TPAD504 = TestLoop: TEST POINT PAD 30MIL DIA SMT, NO PART TO ORDER; AGILE_PN: 211-76642; CAD_APPROVED: Yes; HEIGHT: 0.1MM; MFG_NAME01: NOTACOMPONENT; MFG_PN01: NOTACOMPONENT; ROHS: Yes
TS6 TS9 = TEST_POINT_4: TEST POINT PAD SIZE 3.4MM X 1.8MM SMT; AGILE_PN: 211-75906; CAD_APPROVED: Yes; HEIGHT: 1.53 MM; MFG_NAME01: KEYSTONE ELECTRONICS; MFG_PN01: 5015; PRIORITY_PN: 922-00014; ROHS: Yes
U23 = NC7WP14: IC DUAL INV SCHMITT-TRIG 1.65-5.5V TSOP6; AGILE_PN: TMP-WF-30385; CAD_APPROVED: Yes; HEIGHT: 1.1MM; MFG_NAME01: NEXPERIA; MFG_PN01: 74LVC2G14GV,125; PRE_APN: 312-81771; ROHS: Yes; Temp_Range: -40C to +125C
U24 = MIC2005-0.8YM6: IC LIN SW PWR 0.8A 2.5-5.5V SOT23-6; AGILE_PN: 315-79199; CAD_APPROVED: Yes; HEIGHT: 1.45MM; MFG_NAME01: MICREL; PRIORITY_PN: 051-MIC2005-08; ROHS: Yes; VOLTAGE: 2.5-5.5V
U3 U10 U12 U505 U509 = NTSX2102GU8H_8P: IC DUAL SUPPLY XCVR 50 MBPS 5.5V XQFN8; AGILE_PN: 312-80763; CAD_APPROVED: Yes; HEIGHT: 0.5MM; MFG_NAME01: NXP Semiconductors; ROHS: Yes; VOLTAGE: 5.5V
U510 = PK20DX128V_QFN_32P: IC MCU FLASH 128KB 50MHZ 1.71-3.6V QFN32; AGILE_PN: 344-01231; CAD_APPROVED: Yes; HEIGHT: 1MM; MFG_NAME01: FREESCALE SEMICONDUCTOR; ROHS: Yes; VOLTAGE: 1.71-3.6V
U511 U512 U514 = 74LVCH1T45_6P: IC XCVR 1BIT 3-STATE DUAL 1.2-5.5V XSON6; AGILE_PN: 312-80758; CAD_APPROVED: Yes; HEIGHT: 0.5MM; MFG_NAME01: NEXPERIA; MFG_PN01: 74LVCH1T45GM,132; ROHS: Yes; VOLTAGE: 1.2-5.5V
U513 = 74LVC2T45GM_8P: IC XCVR DUAL SUPPLY 1.2 -5.5V XQFN8; AGILE_PN: 312-80762; CAD_APPROVED: Yes; HEIGHT: 0.5MM; MFG_NAME01: NEXPERIA; ROHS: Yes; VOLTAGE: 5.5V
U515 = RClamp0502A_6P: IC TVS ARRAY LOW CAP 3A 5V SOT666; AGILE_PN: 312-80272; CAD_APPROVED: Yes; HEIGHT: 0.6MM; MFG_NAME01: SEMTECH CORP; ROHS: Yes
Y501 = XTAL_CS: XTAL 8.00MHZ RSN CERAMIC -- SMT; AGILE_PN: 230-77664; CAD_APPROVED: Yes; HEIGHT: 0.8MM; MFG_NAME01: MURATA; MFG_PN01: CSTCE8M00G55-R0; PRIORITY_PN: 048-00290; ROHS: Yes
C17 C28 C529 = CAP_NP: CAP CER 1000PF 25V 5% C0G CC0603; AGILE_PN: 150-75193; CAD_APPROVED: Yes; FPLIST: CC0603_OV,CC0603,0603_CC; HEIGHT: 0.87MM; MFG_NAME01: KEMET; MFG_PN01: C0603C102J3GAC; ROHS: Yes; Tolerance: 5%; VOLTAGE: 25V
C18 C19 C27 C517 C523 C531 = CAP_NP: CAP CER 0.10UF 25V 10% X7R 0603; AGILE_PN: 150-75016; CAD_APPROVED: Yes; FPLIST: CC0603_OV,CC0603,0603_CC; HEIGHT: 0.97 MM; MFG_NAME01: KEMET; MFG_PN01: C0603C104K3RAC; ROHS: Yes; TOL: 10%; Tolerance: 10%; VOLTAGE: 25V
C500 = CAP_NP: CAP CER 0.1UF 50V 10% X7R 0603; AGILE_PN: 150-75142; CAD_APPROVED: Yes; FPLIST: CC0603_OV,CC0603,0603_CC; HEIGHT: 0.9652MM; MFG_NAME01: AVX; MFG_PN01: 06035C104KAT2A; PRIORITY_PN: 021-00295; ROHS: Yes; TOL: 10%; Tolerance: 10%; VOLTAGE: 50V
C547-C549 = CAP_NP: CAP CER 0.1uF 50V 10% X7R 0402; AGILE_PN: 150-79069; CAD_APPROVED: Yes; FPLIST: CC0402_25,CC0402_HD,0402_CC; HEIGHT: 0.55MM; MFG_NAME01: MURATA; MFG_PN01: GRM155R71H104KE14D; ROHS: Yes; Tolerance: 10%; VOLTAGE: 50V
C550 = CAP_NP: CAP CER 10UF 10V 10% X7R 0805; AGILE_PN: 150-78501; CAD_APPROVED: Yes; FPLIST: CC0603_OV,CC0603,0603_CC; HEIGHT: 1.4MM; MFG_NAME01: Murata; MFG_PN01: GRM21BR71A106KE51L; ROHS: Yes; Tolerance: 10%; VOLTAGE: 10V
J16 = QSH030: CON 2X30 SKT SMT 0.5MM SP 120H AU  MOUNTING HOLES TO MATE CABLE HQCD-030-15.00-TBL-TBR-1-SDB; AGILE_PN: 211-75161; CAD_APPROVED: Yes; FPLIST: CON_60S_QSH_SM_A,CON_60S_QSH_SM; HEIGHT: 3.25 MM; MFG_NAME01: SAMTEC; MFG_PN01: QSH-030-01-L-D-A_; ROHS: Yes
L4 = BEAD: IND FER BEAD 120 OHM@100MHZ 500MA 25% 0603; AGILE_PN: 180-75039; CAD_APPROVED: Yes; FPLIST: IND_0603,0603_CC; HEIGHT: 0.95MM; MFG_NAME01: MURATA; MFG_PN01: BLM18AG121SN1J; PART_TYPE: FERRITE; ROHS: Yes; TOL: 25%; Tolerance: 25%
L6 L500 = INDUCTOR_FERRITE: IND FER BEAD 30 OHM@100MHZ 2.2A 25% 0402; AGILE_PN: 180-77768; CAD_APPROVED: Yes; FPLIST: IND_0402,0402_CC; HEIGHT: 0.55MM; MFG_NAME01: Murata; MFG_PN01: BLM15PD300SN1D; PART_TYPE: FERRITE\BEAD; ROHS: Yes; Tolerance: 25%; _DESC: FER_BEAD
R1 R2 R5 R7 R8 R38 R46 R58 R62 R63 R74 R79 R81 R91 R102 R109 R111 R115 = RES: RES MF 33 OHM 1/10W 1% AEC-Q200  0402; AGILE_PN: 470-80961; CAD_APPROVED: Yes; FPLIST: RC0402_25,RC0402_HD,0402_CC; HEIGHT: 0.4 MM; MFG_NAME01: PANASONIC; MFG_PN01: ERJ2RKF33R0X; PCKG: 0402; ROHS: Yes; Tolerance: 1%
R55 R61 R179 R183 R184 R187 R192 R219 R221 R549 R574 = RES: RES MF ZERO OHM 1/16W -- AEC-Q200 0402; AGILE_PN: 470-80742; CAD_APPROVED: Yes; FPLIST: RC0402_25,RC0402_HD,0402_CC; HEIGHT: 0.45 MM; MFG_NAME01: VISHAY INTERTECHNOLOGY; MFG_PN01: CRCW04020000Z0ED; PCKG: 0402; ROHS: Yes
R75 R94 R98 R108 R218 R220 = RES: RES MF ZERO OHM 1/16W -- AEC-Q200 0402; AGILE_PN: 470-80742; ASSY_OPT: DNP; CAD_APPROVED: Yes; FPLIST: RC0402_25,RC0402_HD,0402_CC; HEIGHT: 0.45 MM; MFG_NAME01: VISHAY INTERTECHNOLOGY; MFG_PN01: CRCW04020000Z0ED; PCKG: 0402; ROHS: Yes
R142 R144 R188 R190 R201 R202 R207 R217 R545 = RES: RES MF 10K 1/10W 0.1% AEC-Q200 0603; AGILE_PN: 470-80764; ASSY_OPT: DNP; CAD_APPROVED: Yes; FPLIST: RC0603_OV,RC0603,0603_CC; HEIGHT: 0.55MM; MFG_NAME01: Vishay Intertechnology; MFG_PN01: TNPW060310K0BEEN; ROHS: Yes; Tolerance: 0.1%
R156 R178 R185 R199 R200 R539 R551 R556 = RES: RES MF 10K 1/10W 0.1% AEC-Q200 0603; AGILE_PN: 470-80764; CAD_APPROVED: Yes; FPLIST: RC0603_OV,RC0603,0603_CC; HEIGHT: 0.55MM; MFG_NAME01: Vishay Intertechnology; MFG_PN01: TNPW060310K0BEEN; ROHS: Yes; Tolerance: 0.1%
Y500 = CLKGEN-SM: OSC 50MHZ FIXED 3.3V SMT; AGILE_PN: 230-76894; CAD_APPROVED: Yes; HEIGHT: 1.75MM; MFG_NAME01: ECS INC. INTERNATIONAL; MFG_PN01: ECS-3953M-500-BN; PRIORITY_PN: 048-00175; ROHS: Yes
C532 = CAP_NP: CAP CER 10uF 25V 20% X5R 0603; AGILE_PN: 150-79272; CAD_APPROVED: Yes; FPLIST: CC0603_OV,CC0603,0603_CC; HEIGHT: 1MM; MFG_NAME01: Murata; MFG_PN01: GRM188R61E106MA73D; ROHS: Yes; SIGNAL_MODEL: DEFAULT_CAPACITOR_1e+07pF_2_1; Tolerance: 20%; VOLTAGE: 25V
GND1 = TEST_POINT_3: TEST POINT BLK 70X220 MIL TH; AGILE_PN: 210-30155; CAD_APPROVED: Yes; HEIGHT: 5.6MM; MFG_NAME01: Keystone Electronics; ROHS: Yes
R575 = RES: RES MF 10.0K 1/10W 1% 0603; AGILE_PN: 470-75422; CAD_APPROVED: Yes; FPLIST: RC0603_OV,RC0603,RC0603_CC; HEIGHT: 0.6MM; MFG_NAME01: KOA SPEER; MFG_PN01: RK73H1JTTD1002F; PRIORITY_PN: 006-00378; ROHS: Yes; TOL: 1%; Tolerance: 1%
R581 R585 R586 R590 R591 R595 = RES: RES MF 33 OHM 1/10W 1% AEC-Q200  0402; AGILE_PN: 470-80961; CAD_APPROVED: Yes; FPLIST: RC0402_25,RC0402_HD,0402_CC; HEIGHT: 0.4 MM; MFG_NAME01: PANASONIC; MFG_PN01: ERJ2RKF33R0X; ROHS: Yes; Tolerance: 1%
U508 = MX25L6433FM2R_SOP8: IC MEM FLASH NOR 64Mb SPI SERIAL 2.65-3.6V AUTO R GRADE SOP8; AGILE_PN: 342-00687; CAD_APPROVED: Yes; HEIGHT: 2.16MM; MFG_NAME01: MACRONIX INTERNATIONAL CO., LTD; ROHS: Yes
C78 C108 = CAP_NP: CAP CER 4.7PF 50V 5% C0G 0603; AGILE_PN: 150-79418; CAD_APPROVED: Yes; FPLIST: CC0603_OV,CC0603,0603_CC; HEIGHT: 0.87MM; MFG_NAME01: Kemet; MFG_PN01: C0603C479J5GACTU; ROHS: Yes; Tolerance: 5%; VOLTAGE: 50V
R278 R330 = RES: RES MF 4.7K 1/10W 0.1% AEC-Q200 0603; AGILE_PN: 470-80811; CAD_APPROVED: Yes; FPLIST: RC0603_OV,RC0603,0603_CC; HEIGHT: 0.55MM; MFG_NAME01: YAGEO AMERICA; MFG_PN01: AT0603BRD074K7L; ROHS: Yes; Tolerance: 0.1%
R280 R333 = RES: RES MF ZERO OHM 1/10W -- AEC-Q200 0603; AGILE_PN: 470-75407; CAD_APPROVED: Yes; FPLIST: RC0603_OV,RC0603,R603-X2,0603_CC; HEIGHT: 0.6MM; MFG_NAME01: KOA SPEER; MFG_PN01: RK73Z1JTTD; ROHS: Yes; Tolerance: 1%
SW1 SW2 = ELECTRODE: Capacitive Single Electrode 15MM x 15MM (not a part to order); AGILE_PN: 510-76938; CAD_APPROVED: Yes; FPLIST: electrode_sq_15mm,electrode_sq_15mm_cust; HEIGHT: 0MM; MFG_NAME01: Freescale; MFG_PN01: Single Electrode 15MM x 15MM; ROHS: Yes
C48 C49 = CAP_NP: CAP CER 0.1uF 50V 10% X7R 0402; AGILE_PN: 150-79069; CAD_APPROVED: Yes; FPLIST: CC0402_25,CC0402_HD,0402_CC; HEIGHT: 0.55MM; MFG_NAME01: MURATA; MFG_PN01: GRM155R71H104KE14D; ROHS: Yes; SIGNAL_MODEL: DEFAULT_CAPACITOR_100000pF_2_1; TOL: 10%; Tolerance: 10%; VOLTAGE: 50V
C109 C110 C114 C115 = CAP_NP: CAP CER 0.1uF 50V 10% X7R 0402; AGILE_PN: 150-79069; CAD_APPROVED: Yes; FPLIST: CC0402_25,CC0402_HD,0402_CC; HEIGHT: 0.55MM; MFG_NAME01: MURATA; MFG_PN01: GRM155R71H104KE14D; PRIORITY_PN: 021-00169; ROHS: Yes; SIGNAL_MODEL: DEFAULT_CAPACITOR_100000pF_2_1; Tolerance: 10%; VOLTAGE: 50V
D6 = LED_TRI_COLOR: LED RED/GRN/BL SGL 3-IN-1 50mA SMT; AGILE_PN: 370-76661; CAD_APPROVED: Yes; HEIGHT: 2.6 MM; MFG_NAME01: Cree, Inc; MFG_PN01: CLP6C-FKB-CM1Q1H1BB7R3R3; ROHS: Yes
Q1-Q3 = NPN: TRAN NPN GEN AMP 200MA 40V AEC-Q101 SC75; AGILE_PN: 480-75477; CAD_APPROVED: Yes; HEIGHT: 0.9 MM; MFG_NAME01: ON SEMICONDUCTOR; ROHS: Yes
R186 = POT: RES POT 5K 1/2W 20% TH; AGILE_PN: 470-80115; CAD_APPROVED: Yes; HEIGHT: 4.32 MM; MFG_NAME01: BOURNS; MFG_PN01: 3352T-1-502LF; ROHS: Yes; TOL: 20%; Tolerance: 20%
R194 R306 R307 = RES: RES MF 220 OHM 1/10W 5% 0603; AGILE_PN: 470-30297; CAD_APPROVED: Yes; FPLIST: RC0603_OV,RC0603,0603_CC; HEIGHT: 0.6MM; MFG_NAME01: KOA SPEER; MFG_PN01: RK73B1JTTD221J; ROHS: Yes; Tolerance: 5%
R228 R248 R257 = RES: RES MF 33K  1/16W 1% 0402; AGILE_PN: 470-31004; CAD_APPROVED: Yes; FPLIST: RC0402_25,RC0402_HD,0402_CC; HEIGHT: 0.40 MM; MFG_NAME01: KOA SPEER; MFG_PN01: RK73H1ETTP3302F; ROHS: Yes; Tolerance: 1%
R229 R247 R256 = RES: RES MF 560 1/10W 5% 0603; AGILE_PN: 470-30301; CAD_APPROVED: Yes; FPLIST: RC0603_OV,RC0603,0603_CC; HEIGHT: 0.6MM; MFG_NAME01: YAGEO AMERICA; MFG_PN01: RC0603JR-07560RL; ROHS: Yes; SIGNAL_MODEL: DEFAULT_RESISTOR_560.000000OHM_2_1; TOL: 5%; Tolerance: 5%
TP27 = TESTLOOP: TEST POINT PAD 28MIL DIA SMT, NO PART TO ORDER; AGILE_PN: 211-79313; CAD_APPROVED: Yes; HEIGHT: 0.1 MM; MFG_NAME01: N/A; MFG_PN01: N/A; ROHS: Yes
TP42-TP44 TP46 TP48 TP49 TP60 TP61 TP506 TP507 = TestLoop: TEST POINT PAD 28MIL DIA SMT, NO PART TO ORDER; AGILE_PN: 211-79313; CAD_APPROVED: Yes; HEIGHT: 0.1 MM; MFG_NAME01: N/A; MFG_PN01: N/A; ROHS: Yes

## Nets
GND: C17.2 C18.2 C19.2 C27.2 C28.2 C48.2 C49.2 C78.2 C89.2 C97.2 C108.2 C109.2 C110.2 C111.2 C114.2 C115.2 C500.2 C517.2 C523.2 C529.2 C531.2 C532.2 C533.2 C534.2 C535.2 C536.2 C537.2 C538.2 C539.2 C540.2 C541.2 C542.2 C543.2 C544.2 C545.2 C546.2 C547.2 C548.2 C549.2 C550.2 GND1.1 J16.2 J16.6 J16.11 J16.12 J16.18 J16.22 J16.26 J16.29 J16.30 J16.34 J16.40 J16.46 J16.SH1 J16.SH2 J16.SH3 J16.SH4 J20.3(A2) J20.5(A3) J24.5(GND) L501.2 Q1.2(EMITTER) Q2.2(EMITTER) Q3.2(EMITTER) R186.3(B) R228.2 R248.2 R257.2 R296.2 R335.2 R336.2 R608.2 R612.2 R623.2 R626.2 R629.2 R630.2 SW5.1 SW5.3 U3.4(GND) U10.4(GND) U12.4(GND) U23.2(GND) U24.2(GND) U505.4(GND) U508.4(GND) U509.4(GND) U510.2(VSS1) U510.8(VSSA) U510.33(EPAD) U511.2(GND) U512.2(GND) U513.3(DIR) U513.4(GND) U514.2(GND) U515.2(GND) Y500.2(GND) Y501.2 ; also on sheet 1 2 3 4 11
P3V3_ENET: C549.1 C550.1 J16.1 J16.3 L4.2 R133.2 TPAD28.1(Pin1)
P3V3_ENETSW: C17.1 C18.1 C19.1 R142.1 R144.1 R185.1 R199.1 R201.1 R202.1 R521.1 R522.1 R551.1 R556.1 TPAD31.1(Pin1) U3.8(VCCB) U10.8(VCCB) U12.8(VCCB) U505.8(VCCB)
P3V3_SDA: C97.1 C533.1 C535.1 C536.1 C538.1 C539.1 C540.1 C545.1 J20.1(A1) R281.1 R285.2 R286.1 R288.1 R291.1 R301.1 R308.1 R605.1 R606.1 R607.1 R610.1 R613.1 R616.1 R621.1 R622.1 R631.1 TP55.1(Pin1) TPAD48.1(Pin1) U23.5(VCC) U509.1(VCCA) U510.1(VDD1) U510.7(VDDA) U510.11(VBAT) U511.1(VCCA) U512.1(VCCA) U513.7(VCCA) U514.1(VCCA)
P3V3_SW: L4.1 L500.2 R41.1 R133.1 R288.2 R501.2 R521.2 R574.2 ; also on sheet 1 2 4 11
P5V0: D6.A1(ANODE1) D6.A2(ANODE2) D6.A3(ANODE3) R6.1 R35.1 R522.2 ; also on sheet 1 2 4 11
P5V0_SDA_USB_CONN_VBUS: J24.1(VBUS) L9.1 U515.5(VCC)
P5V_SDA: C89.1 C103.1 C111.1 L9.2 R293.1 R615.1 R628.1 U24.1(VIN) U510.6(VREGIN)
P5V_SDA_PSW: TPAD49.1(Pin1) U24.6(VOUT) ; also on sheet 2
VCC_HYPRFLASH: C529.1 C531.1 C532.1 L500.1 R574.1 R575.1 TPAD504.1(Pin1) U508.8(VCC)
VDD: R299.2 ; also on sheet 2
VDD_MCU_ENETSW: C27.1 C28.1 C517.1 L6.2 R156.1 R178.1 R179.2 R188.1 R190.1 R200.1 R207.1 R217.1 R539.1 R545.1 TPAD36.1(Pin1) U3.1(VCCA) U10.1(VCCA) U12.1(VCCA) U505.1(VCCA)
VDD_MCU_PERH: L6.1 R161.2 R179.1 SW3.1 SW3.3 SW4.1 SW4.3 ; also on sheet 2 3 4 11
ADC_POT: C48.1 R194.2 TP27.1(Pin1) ; also on sheet 3
ENET_MII_TXC: J16.20 R96.1 R513.1 R514.1 TPAD21.1(Pin1)
ENETSW_INH: R2.2 R556.2 TPAD503.1(Pin1) U505.7(B1)
ENETSW_RESET: R1.2 ; also on sheet 4
ENETSW_SCL: R7.2 R199.2 TPAD3.1(Pin1) U10.6(B2)
ENETSW_SDA: R8.2 R185.2 TPAD5.1(Pin1) U10.7(B1)
ENETSW_SPI_MISO: R75.1 R202.2 TPAD13.1(Pin1) U12.6(B2)
ENETSW_SPI_MOSI: R108.1 R142.2 TPAD33.1(Pin1) U3.7(B1)
ENETSW_SPI_SC: R94.1 R201.2 TPAD37.1(Pin1) U12.7(B1)
ENETSW_SPI_SCK: R98.1 R144.2 TPAD34.1(Pin1) U3.6(B2)
HYPFLASH/QSPI_A_CS: R575.2 R581.2 U508.1(~{CS})
HYPFLASH/QSPI_A_IO0: R595.2 U508.5(SI/SIO0)
HYPFLASH/QSPI_A_IO1: R585.2 U508.2(SO/SIO1)
HYPFLASH/QSPI_A_IO2: R590.2 U508.3(~{W}P/SIO2)
HYPFLASH/QSPI_A_IO3: R586.2 U508.7(~{HOLD}/SIO3)
HYPFLASH/QSPI_A_SCK: R591.2 U508.6(SCLK)
LED_BLUE: R222.2 ; also on sheet 3
LED_GREEN: R245.2 ; also on sheet 3
LED_RED: R255.2 ; also on sheet 3
LEDRGB_BLUE: D6.C3(CATHODE3) R229.1 TP43.1(Pin1)
LEDRGB_GREEN: D6.C2(CATHODE2) R247.1 TP46.1(Pin1)
LEDRGB_RED: D6.C1(CATHODE1) R256.1 TP48.1(Pin1)
LVLRST_EN: R610.2 U509.5(OE)
MIC2005_CSLEW: C103.2 U24.5(CSLEW)
POWER_EN: R300.1 U510.31(ADC0_SE7B/PTD6/SPI0_PCS3/UART0_RX/FTM0_CH6/FTM0_FLT0/LLWU_P15)
PTA4/CMP0_OUT/JTAG_TMS/SWD_DIO: R294.2 ; also on sheet 3
PTA5/TCLK1_2/RESET: D11.C(CATHODE) J22.1 R289.2 R295.2 TS6.1 ; also on sheet 2 3 4 11
PTB4/MII_RMII_MDIO: R46.2 ; also on sheet 4
PTB5/ENET_MII_RMII_MDC: R38.2 ; also on sheet 4
PTB9/FTM3_CH1/LPI2C0_SCLS: R192.1 ; also on sheet 1 3 11
PTB10/FTM3_CH2/LPI2C0_SDAS: R187.1 ; also on sheet 1 3 11
PTB20/FTM6_CH0/ENET_INT: R5.2 ; also on sheet 4
PTB25/FTM6_CH5/LPSPI2_PCS0/ADC0_SE21: R218.1 ; also on sheet 3 11
PTB27/FTM6_CH7/LPSPI2_SOUT/ADC0_SE22: R221.1 ; also on sheet 3 11
PTB28/FTM7_CH0/LPSPI2_SIN/ADC0_SE23: R183.1 ; also on sheet 3 11
PTB29/FTM7_CH1/LPSPI2_SCK/ADC0_SE24: R184.1 ; also on sheet 3 11
PTC0/MII_RMII_RXD1: R63.2 ; also on sheet 4
PTC1/MII_RMII_RXD0: R74.2 ; also on sheet 4
PTC2/MII_RMII_TXD0: R102.2 ; also on sheet 4
PTC2/QSPI_A_IO3: R586.1 ; also on sheet 4
PTC3/MII_TX_ER: R55.1 ; also on sheet 4
PTC3/QSPI_A_CS: R581.1 ; also on sheet 4
PTC4/FTM1_CH0/RTC_CLKOUT/JTAG_TCLK/SWD_CLK: R298.2 ; also on sheet 3
PTC6/LPUART1_RX/CAN1_RX/FTM3_CH2: R627.2 ; also on sheet 3 11
PTC7/LPUART1_TX/CAN1_TX/FTM3_CH3: R620.2 ; also on sheet 3 11
PTC8/LPUART1_RX: R305.2 ; also on sheet 3 11
PTC9/LPUART1_TX: R619.2 ; also on sheet 3 11
PTC12/BTN0: C109.1 R306.2 TP507.1(Pin1) ; also on sheet 3
PTC13/BTN1: C110.1 R307.2 TP506.1(Pin1) ; also on sheet 3
PTC16/MII_RMII_RX_ER: R61.1 ; also on sheet 4
PTC17/MII_RMII_RX_DV: R81.2 ; also on sheet 4
PTD5/MII_TXD3: R115.2 ; also on sheet 4
PTD6/MII_TXD2: R111.2 ; also on sheet 4
PTD7/MII_RMII_TXD1: R109.2 ; also on sheet 4
PTD7/QSPI_A_IO1: R585.1 ; also on sheet 4
PTD8/MII_RXD3: R58.2 ; also on sheet 4
PTD9/MII_RXD2: R62.2 ; also on sheet 4
PTD10/MII_RX_CLK: R79.2 R96.2 R137.2 ; also on sheet 4
PTD10/QSPI_A_SCK: R591.1 ; also on sheet 4
PTD11/MII_RMII_TX_CLK: R123.2 R514.2 ; also on sheet 4
PTD11/QSPI_A_IO0: R595.1 ; also on sheet 4
PTD12/MII_RMII_TX_EN: R91.2 ; also on sheet 4
PTD12/QSPI_A_IO2: R590.1 ; also on sheet 4
PTD29/FTM7_CH2/FTM7_CH2/ADC1_SE23: R549.1 ; also on sheet 3 11
PTE10/CLKOUT/LPSPI2_PCS1/FTM2_CH4/FXIO_D4: R219.1 ; also on sheet 1 3 11
PTE13/FTM4_CH5/LPSPI2_PCS2/FTM2_FLT0: R220.1 ; also on sheet 3 11
SDA_EXTAL: C534.1 U510.17(EXTAL0/PTA18/FTM0_FLT2/FTM_CLKIN0) Y501.3
SDA_JTAG_TCLK: J20.4(B2) R608.1 U510.12(JTAG_TCLK/SWD_CLK/EZP_CLK/TSI0_CH1/PTA0/~{UART0_CTS}/~{UART0_COL}/FTM0_CH5)
SDA_JTAG_TDI: J20.8(B4) R281.2 U510.13(JTAG_TDI/EZP_DI/TSI0_CH2/PTA1/UART0_RX/FTM0_CH6)
SDA_JTAG_TDO: J20.6(B3) R605.2 U510.14(JTAG_TDO/TRACE_SWO/EZP_DO/TSI0_CH3/PTA2/UART0_TX/FTM0_CH7)
SDA_JTAG_TMS: J20.2(B1) R606.2 U510.15(JTAG_TMS/SWD_DIO/TSI0_CH4/PTA3/~{UART0_RTS}/FTM0_CH0)
SDA_LED: D10.C(CATHODE) U510.29(PTD4/SPI0_PCS1/~{UART0_RTS}/FTM0_CH4/EWM_IN/LLWU_P14)
SDA_LED_R: D10.A(ANODE) R308.2
SDA_RST: J20.10(B5) R607.2 R612.1 R615.2 TP510.1(Pin1) U510.19(~{RESET})
SDA_RST_LED: D11.A(ANODE) R337.1
SDA_RST_TGTMCU_B: J23.2 U510.21(ADC0_SE9/TSI0_CH6/PTB1/I2C0_SDA/FTM1_CH1/FTM1_QD_PHB)
SDA_RST_TGTMCU_J_B: J22.3 J23.1 R295.1 R616.2 U509.2(A1)
SDA_RX_EN: R630.1 R631.2 U514.5(DIR)
SDA_SPI0_CS: R290.2 TP511.1(Pin1) U510.23(ADC0_SE4B/CMP1_IN0/TSI0_CH15/PTC2/SPI0_PCS2/~{UART1_CTS}/FTM0_CH1/I2S0_TX_FS)
SDA_SPI0_RST_B: R292.2 TP57.1(Pin1) U510.22(ADC0_SE15/TSI0_CH14/PTC1/SPI0_PCS3/~{UART1_RTS}/FTM0_CH0/I2S0_TXD0/LLWU_P6)
SDA_SPI0_SCK: U510.26(PTC5/SPI0_SCK/LPTMR0_ALT2/I2S0_RXD0/CMP0_OUT/LLWU_P9) U511.3(A)
SDA_SPI0_SIN: U510.28(CMP0_IN1/PTC7/SPI0_SIN/USB_SOF_OUT/I2S0_RX_FS) U513.5(2A)
SDA_SPI0_SOUT: U510.27(CMP0_IN0/PTC6/SPI0_SOUT/PDB0_EXTRG/I2S0_RX_BCLK/I2S0_MCLK/LLWU_P10) U512.3(A)
SDA_SWD_EN: R292.1 R624.1 U23.6(Y1)
SDA_SWD_EN_B: R609.2 U510.16(~{NMI}/~{EZP_CS}/TSI0_CH5/PTA4/FTM0_CH1/LLWU_P3)
SDA_SWD_EN_B_R: R286.2 R609.1 U23.1(A1)
SDA_SWD_EN_R: R622.2 R623.1 R624.2 U511.5(DIR)
SDA_SWD_OE: R290.1 R625.1 U23.4(Y2)
SDA_SWD_OE_B: R284.2 U510.20(ADC0_SE8/TSI0_CH0/PTB0/I2C0_SCL/FTM1_CH0/FTM1_QD_PHA/LLWU_P5)
SDA_SWD_OE_B_R: R284.1 R285.1 U23.3(A2)
SDA_SWD_OE_R: R621.2 R625.2 R626.1 U512.5(DIR)
SDA_USB_CONN_DN: J24.2(D-) U515.6(D+)
SDA_USB_CONN_DP: J24.3(D+) U515.4(D-)
SDA_USB_DN: R617.2 U510.4(USB0_DM)
SDA_USB_DP: R618.2 U510.3(USB0_DP)
SDA_USB_P5V_SENSE: R628.2 R629.1 U510.30(ADC0_SE6B/PTD5/SPI0_PCS2/~{UART0_CTS}/~{UART0_COL}/FTM0_CH5/~{EWM_OUT})
SDA_USBSHIELD: J24.6(SHELL1) J24.7(SHELL2) J24.8(SHELL3) J24.9(SHELL4) J24.10(SHELL5) L501.1
SDA_VOUT33: C541.1 R291.2 U510.5(VOUT33)
SDA_XTAL: C537.1 U510.18(XTAL0/PTA19/FTM1_FLT0/FTM_CLKIN1/LPTMR0_ALT1) Y501.1
SW1_RST_B: C543.1 J22.2 SW5.2 SW5.4
SWD_CLK_TGTMCU_BUF: R298.1 U511.4(B)
SWD_DIO_TGTMCU_BUF: R294.1 U512.4(B) U513.2(2B)
TC_EXTAL_TP: TP508.1(Pin1) U510.10(EXTAL32)
TC_SDA_USB_ID_TP: J24.4(ID) TP512.1(Pin1)
TC_XTAL_TP: TP509.1(Pin1) U510.9(XTAL32)
TOUCH_ADC0_A: C108.1 R330.1 TPAD52.1(Pin1) ; also on sheet 3
TOUCH_ADC0_B: C78.1 R278.1 TPAD46.1(Pin1) ; also on sheet 3
TOUCH_ADC1_A: R330.2 R333.1 TPAD53.1(Pin1) ; also on sheet 3
TOUCH_ADC1_B: R278.2 R280.1 TPAD47.1(Pin1) ; also on sheet 3
UART1_RX_TGTMCU_BUF: R305.1 R627.1 U514.4(B)
UART1_RX_TGTMCU_R: U510.25(PTC4/SPI0_PCS0/UART1_TX/FTM0_CH3/CMP1_OUT/LLWU_P8) U514.3(A)
UART1_TX_TGTMCU_BUF: R619.1 R620.1 U513.1(1B)
UART1_TX_TGTMCU_R: U510.24(CMP1_IN1/PTC3/SPI0_PCS1/UART1_RX/FTM0_CH2/I2S0_TX_BCLK/LLWU_P7) U513.6(1A)
V_TGTMCU: C542.1 C544.1 C546.1 R299.1 R337.2 R611.1 R614.1 TPAD54.1(Pin1) U509.8(VCCB) U511.6(VCCB) U512.6(VCCB) U513.8(VCCB) U514.6(VCCB)
VSUP: R3.1 ; also on sheet 2
VTRG_EN: R293.2 R296.1 R300.2 U24.3(ENABLE)
VTRG_FAULT_B: R301.2 U24.4(~{FAULT}) U510.32(PTD7/CMT_IRO/UART0_TX/FTM0_CH7/FTM0_FLT1)
N12195: C114.1 R306.1 R335.1 SW3.2 SW3.4 TP60.1(Pin1)
N12333: Q1.3(COLLECTOR) R229.2 TP42.1(Pin1)
N12731: C49.1 R186.2(WIPER) R194.1 TS9.1
N14568: C115.1 R307.1 R336.1 SW4.2 SW4.4 TP61.1(Pin1)
N16876903: Q2.3(COLLECTOR) R247.2 TP44.1(Pin1)
N16876912: Q3.3(COLLECTOR) R256.2 TP49.1(Pin1)
N16877035: Q1.1(BASE) R222.1 R228.1 TPAD38.1(Pin1)
N16877205: Q2.1(BASE) R245.1 R248.1 TPAD41.1(Pin1)
N16877232: Q3.1(BASE) R255.1 R257.1 TPAD43.1(Pin1)
N16979800: R161.1 R186.1(A)
N17033217: J16.60 R1.1
N17033342: J16.50 R38.1
N17036679: J16.4 R123.1 R137.1
N17037130: J16.10 R111.1
N17037131: J16.8 R115.1
N17037133: J16.42 R62.1
N17037134: J16.44 R58.1
N17037135: J16.28 R81.1
N17037137: J16.36 R74.1
N17037138: J16.38 R63.1
N17037139: J16.16 R102.1
N17037140: J16.32 R79.1
N17037141: J16.14 R109.1
N17037142: J16.24 R91.1
N17037216: J16.48 R46.1
N17037599: C500.1 R501.1 Y500.1(OE) Y500.4(VDD)
N17039052: J16.56 R5.1
N17047156: C547.1 J16.57 R35.2 R41.2 TPAD4.1(Pin1)
N17049594: R513.2 Y500.3(CLKOUT)
N17049891: C548.1 J16.59 R3.2 R6.2 TPAD1.1(Pin1)
N17061413: J16.52 R8.1
N17061419: J16.54 R7.1
N17062294: J16.47 R61.2
N17062316: J16.55 R55.2
N17063944: J16.5 TPAD25.1(Pin1)
N17070752: J16.15 TPAD22.1(Pin1)
N17070755: J16.17 TPAD19.1(Pin1)
N17070986: R207.2 R218.2 R219.2 R220.2 U12.2(A1)
N17073684: R183.2 R184.2 R188.2 R190.2 U3.2(A1) U3.3(A2)
N17074032: R217.2 R221.2 U12.3(A2)
N17074703: C523.1 R156.2 U3.5(OE) U10.5(OE) U12.5(OE) U505.5(OE)
N17076548: R178.2 R187.2 U10.2(A1)
N17076571: R192.2 R200.2 U10.3(A2)
N17077988: J16.31 R75.2
N17078013: J16.13 R94.2
N17078038: J16.9 R98.2
N17078063: J16.7 R108.2
N17085305: R617.1 U515.1(D+_PC)
N17085321: R618.1 U515.3(D-_PC)
N17090620: R611.2 U509.6(B2)
N17093251: R613.2 U509.3(A2)
N17094456: R289.1 R614.2 U509.7(B1)
N17109048: J16.58 R2.1
N17322992: J16.23 TPAD18.1(Pin1)
N17322995: J16.27 TPAD16.1(Pin1)
N17323030: J16.41 TPAD11.1(Pin1)
N17323033: J16.43 TPAD10.1(Pin1)
N17381520: R545.2 R549.2 U505.2(A1)
N17382056: R539.2 U505.3(A2)
N17382061: R551.2 U505.6(B2)
N20712518: R333.2 SW2.1
N20712658: R280.2 SW1.1

Not connected (* = marked no-connect by the designer): J16 19* 21* 25* 33* 35* 37* 39* 45* 49* 51* 53*; J20 7(A4)* 9(A5)*

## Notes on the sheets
sheet 5
- OpenSDA Interface
- RESET
- RST
  Push
  Button
  Bypass
- TARGET MCU
  INTERFACE
  SIGNALS
- Output to system
  from Level shifter
- UART1_RX_TGTMCU
- UART1_RX_TGTMCU
- Isolation
  Resistors
- Output to system
  from Level shifter
- UART1_TX_TGTMCU
- UART1_TX_TGTMCU
- PU/PD LOGIC:
  SERIAL INTERFACE
  IS ALWAYS RESET
  WHEN USB PORT
  IS DISCONNECTED
- Output to system
  from Level shifter
- SWD_DIO_TGTMCU
- JTAG
- SWD_DIO_TGTMCU
- JTAG
- HW Designer: Rafael del Rey
- OPEN SDA
  POWER OUTPUTS
- OPEN SDA
  INPUT POWER
- i
- path
- i
- path
- Note: You can power openSDA
  with your own power supplies
  by replacing this rail
  (SDA_VOUT33)
  with your 3.3V power supply rail
- 3.3VDC, 10mA should be provided
  to this rail (P3V3_SDA)
  in order to power openSDA
  module
- SHORTING HEADER ON BOTTOM LAYER
  Jumper is shorted by a cut-trace
  on bottom layer. Cutting the trace
  will effectively isolate the on-board
  MCU from the OpenSDA
  debug interface.
- OpenSDA INTERFACE JTAG CONNECTOR
- Isolation and level shift stage
  (for 1.8 to 5V compatibility)
- PU/PD LOGIC (DIR PIN):
  BUFFER IS TRISTATED WHEN
  P3V3_SDA IS UNPOWERED
- i
- path
- PWR SWITCH
- SDA_VOUT33 can provide up to 120mA
  of power at 3.3VDC to your system
  P5V_TRG_SDA can provide up to 450mA
  (per USB spec) of power at 5VDC
  to your system
- (To enable 5v from
  USB connector)
- ACTIVE HIGH
- i
- I/O POWER
  INPUT
- path
- V_BRD is supported
  from 1.8V to 5V
- 3.3 V / 5.0V
  MCU Reference
- Power should be provided
  to this rail for the logic
  related to your platform I/O
- {For enablement purposes only}
sheet 6
- Mating conn = Samtec QTH series
  Compatible Ethernet Daughter Card
  ----------------------------------
  NXPU_MXEK
- SPI_MOSI
- SPI_SCK
- SPI_CS
- SPI_MISO
- Ethernet Card RESET
- 3.3 V / 5.0V
  MCU Reference
- 3.3 Volts
  by Default
- ENET_SPI_MOSI
- SPI_MOSI
- ENET_SPI_SCK
- SPI_SCK
- ENET_SPI_CS0
- ENET_SPI_CS1
- ENET_SPI_CS2
- SPI_CS
- ENET_SPI_MISO
- SPI_MISO
- ENET_I2C_SDA
- ENET_I2C_SCL
sheet 7
- CMOS FLASH Memory 64M-BIT
- ENET
- HYPFLASH
- ENET
- HYPFLASH
- ENET
- HYPFLASH
- ENET
- HYPFLASH
- ENET
- HYPFLASH
- ENET
- HYPFLASH
sheet 8
- TOUCH
- Touch PADs
- TOUCH
sheet 9
- User buttons
- RGB LED
- 3.3 V / 5.0V
  MCU Reference
- Potentiometer
sheet 10
- X-S32K148EVBQ144/Q176
- C U S T O M E R   E V B
- Table of Contents
- Revisions
- 01   TITLE AND NOTES
- Rev
- Description
- Designer
- Date
- Approved
- 02   POWER SUPPLY / LIN / CAN
- X4
- Schematic
- J.Sanchez
- 03   S32K148 MCU
- A
- Prototype
- 04   VOLTAGE TRANSLATORS
- C
- First Release
- 05   OPEN SDA
- 06   ETHERNET
- 07   FLASH MEM
- 08   SAI AUDIO
- 09   I/Os HEADERS
- 10   TOUCH
- 11   USER I/Os
- C A U T I O N :
- This schematic is provided for reference
  purposes only. As such, NXP does not make any
  warranty, implied or otherwise, as to the
  suitability of circuit design or component
  selection (type or value) used in these
  schematics for hardware design using the  NXP
  S32K family of Microprocessors. Customers using
  any part of these schematics as a basis for
  hardware design, do so at their own risk and
  Freescale does not assume any liability for such
  a hardware design.
- 3 Different test points
  used in design:
  TPVx - Through Hole Pad
  small
  TPHx - Through Hile Pad
  Large (for standard 0.1"
  header). Also used on IO
  Matrix (IOMx)
  TPX  - Surface Mount Wire
  Loop
- Notes:
- - All components and board processes are to be ROHS compliant
  - All connectors and headers are denoted Jx/Px and are 2.54mm pitch unless otherwise stated
  - All jumpers are denoted Jx. Jumpers are 2mm pitch
  - Jumper default positions are shown in the schematics. For 3 way jumpers, default is always
  posn 1-2.
    2 Pin jumpers generally have the "source" on pin 1.
  - All switches are denoted SWx
  - All test points (SMT wire loop style) are denoted TPx
  - Test point Vias (just through hole pads) are denoted TPVx
- Signals (ports) have not been routed via busses as this makes it harder to determine
  where each signal goes.
- User notes are given throughtout the schematics.
- Specific PCB LAYOUT notes are detailed in ITALICS
